VERSION 5.8 ;
BUSBITCHARS "[]" ;
DIVIDERCHAR "/" ;
UNITS
    DATABASE MICRONS 1000 ;
END UNITS

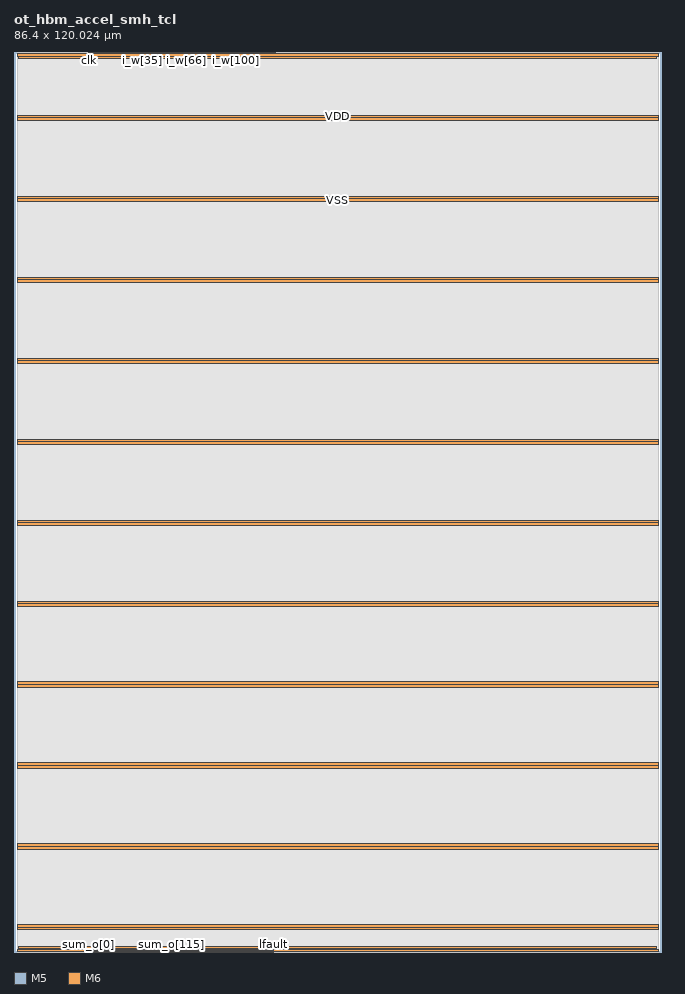
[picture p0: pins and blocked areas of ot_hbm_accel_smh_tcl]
MACRO ot_hbm_accel_smh_tcl
  FOREIGN ot_hbm_accel_smh_tcl 0 0 ;
  CLASS BLOCK ;
  SIZE 86.4 BY 120.024 ;
  PIN clk
    DIRECTION INPUT ;
    USE SIGNAL ;
    PORT
      LAYER M5 ;
        RECT  9.984 119.832 10.008 120.024 ;
    END
  END clk
  PIN i_first
    DIRECTION INPUT ;
    USE SIGNAL ;
    PORT
      LAYER M5 ;
        RECT  10.272 119.832 10.296 120.024 ;
    END
  END i_first
  PIN i_v
    DIRECTION INPUT ;
    USE SIGNAL ;
    PORT
      LAYER M5 ;
        RECT  10.176 119.832 10.2 120.024 ;
    END
  END i_v
  PIN i_w[0]
    DIRECTION INPUT ;
    USE SIGNAL ;
    PORT
      LAYER M5 ;
        RECT  10.368 119.832 10.392 120.024 ;
    END
  END i_w[0]
  PIN i_w[100]
    DIRECTION INPUT ;
    USE SIGNAL ;
    PORT
      LAYER M5 ;
        RECT  29.568 119.832 29.592 120.024 ;
    END
  END i_w[100]
  PIN i_w[101]
    DIRECTION INPUT ;
    USE SIGNAL ;
    PORT
      LAYER M5 ;
        RECT  29.76 119.832 29.784 120.024 ;
    END
  END i_w[101]
  PIN i_w[102]
    DIRECTION INPUT ;
    USE SIGNAL ;
    PORT
      LAYER M5 ;
        RECT  29.952 119.832 29.976 120.024 ;
    END
  END i_w[102]
  PIN i_w[103]
    DIRECTION INPUT ;
    USE SIGNAL ;
    PORT
      LAYER M5 ;
        RECT  30.144 119.832 30.168 120.024 ;
    END
  END i_w[103]
  PIN i_w[104]
    DIRECTION INPUT ;
    USE SIGNAL ;
    PORT
      LAYER M5 ;
        RECT  30.336 119.832 30.36 120.024 ;
    END
  END i_w[104]
  PIN i_w[105]
    DIRECTION INPUT ;
    USE SIGNAL ;
    PORT
      LAYER M5 ;
        RECT  30.528 119.832 30.552 120.024 ;
    END
  END i_w[105]
  PIN i_w[106]
    DIRECTION INPUT ;
    USE SIGNAL ;
    PORT
      LAYER M5 ;
        RECT  30.72 119.832 30.744 120.024 ;
    END
  END i_w[106]
  PIN i_w[107]
    DIRECTION INPUT ;
    USE SIGNAL ;
    PORT
      LAYER M5 ;
        RECT  30.912 119.832 30.936 120.024 ;
    END
  END i_w[107]
  PIN i_w[108]
    DIRECTION INPUT ;
    USE SIGNAL ;
    PORT
      LAYER M5 ;
        RECT  31.104 119.832 31.128 120.024 ;
    END
  END i_w[108]
  PIN i_w[109]
    DIRECTION INPUT ;
    USE SIGNAL ;
    PORT
      LAYER M5 ;
        RECT  31.296 119.832 31.32 120.024 ;
    END
  END i_w[109]
  PIN i_w[10]
    DIRECTION INPUT ;
    USE SIGNAL ;
    PORT
      LAYER M5 ;
        RECT  12.288 119.832 12.312 120.024 ;
    END
  END i_w[10]
  PIN i_w[110]
    DIRECTION INPUT ;
    USE SIGNAL ;
    PORT
      LAYER M5 ;
        RECT  31.488 119.832 31.512 120.024 ;
    END
  END i_w[110]
  PIN i_w[111]
    DIRECTION INPUT ;
    USE SIGNAL ;
    PORT
      LAYER M5 ;
        RECT  31.68 119.832 31.704 120.024 ;
    END
  END i_w[111]
  PIN i_w[112]
    DIRECTION INPUT ;
    USE SIGNAL ;
    PORT
      LAYER M5 ;
        RECT  31.872 119.832 31.896 120.024 ;
    END
  END i_w[112]
  PIN i_w[113]
    DIRECTION INPUT ;
    USE SIGNAL ;
    PORT
      LAYER M5 ;
        RECT  32.064 119.832 32.088 120.024 ;
    END
  END i_w[113]
  PIN i_w[114]
    DIRECTION INPUT ;
    USE SIGNAL ;
    PORT
      LAYER M5 ;
        RECT  32.256 119.832 32.28 120.024 ;
    END
  END i_w[114]
  PIN i_w[115]
    DIRECTION INPUT ;
    USE SIGNAL ;
    PORT
      LAYER M5 ;
        RECT  32.448 119.832 32.472 120.024 ;
    END
  END i_w[115]
  PIN i_w[116]
    DIRECTION INPUT ;
    USE SIGNAL ;
    PORT
      LAYER M5 ;
        RECT  32.64 119.832 32.664 120.024 ;
    END
  END i_w[116]
  PIN i_w[117]
    DIRECTION INPUT ;
    USE SIGNAL ;
    PORT
      LAYER M5 ;
        RECT  32.832 119.832 32.856 120.024 ;
    END
  END i_w[117]
  PIN i_w[118]
    DIRECTION INPUT ;
    USE SIGNAL ;
    PORT
      LAYER M5 ;
        RECT  33.024 119.832 33.048 120.024 ;
    END
  END i_w[118]
  PIN i_w[119]
    DIRECTION INPUT ;
    USE SIGNAL ;
    PORT
      LAYER M5 ;
        RECT  33.216 119.832 33.24 120.024 ;
    END
  END i_w[119]
  PIN i_w[11]
    DIRECTION INPUT ;
    USE SIGNAL ;
    PORT
      LAYER M5 ;
        RECT  12.48 119.832 12.504 120.024 ;
    END
  END i_w[11]
  PIN i_w[120]
    DIRECTION INPUT ;
    USE SIGNAL ;
    PORT
      LAYER M5 ;
        RECT  33.408 119.832 33.432 120.024 ;
    END
  END i_w[120]
  PIN i_w[121]
    DIRECTION INPUT ;
    USE SIGNAL ;
    PORT
      LAYER M5 ;
        RECT  33.6 119.832 33.624 120.024 ;
    END
  END i_w[121]
  PIN i_w[122]
    DIRECTION INPUT ;
    USE SIGNAL ;
    PORT
      LAYER M5 ;
        RECT  33.792 119.832 33.816 120.024 ;
    END
  END i_w[122]
  PIN i_w[123]
    DIRECTION INPUT ;
    USE SIGNAL ;
    PORT
      LAYER M5 ;
        RECT  33.984 119.832 34.008 120.024 ;
    END
  END i_w[123]
  PIN i_w[124]
    DIRECTION INPUT ;
    USE SIGNAL ;
    PORT
      LAYER M5 ;
        RECT  34.176 119.832 34.2 120.024 ;
    END
  END i_w[124]
  PIN i_w[125]
    DIRECTION INPUT ;
    USE SIGNAL ;
    PORT
      LAYER M5 ;
        RECT  34.368 119.832 34.392 120.024 ;
    END
  END i_w[125]
  PIN i_w[126]
    DIRECTION INPUT ;
    USE SIGNAL ;
    PORT
      LAYER M5 ;
        RECT  34.56 119.832 34.584 120.024 ;
    END
  END i_w[126]
  PIN i_w[127]
    DIRECTION INPUT ;
    USE SIGNAL ;
    PORT
      LAYER M5 ;
        RECT  34.752 119.832 34.776 120.024 ;
    END
  END i_w[127]
  PIN i_w[12]
    DIRECTION INPUT ;
    USE SIGNAL ;
    PORT
      LAYER M5 ;
        RECT  12.672 119.832 12.696 120.024 ;
    END
  END i_w[12]
  PIN i_w[13]
    DIRECTION INPUT ;
    USE SIGNAL ;
    PORT
      LAYER M5 ;
        RECT  12.864 119.832 12.888 120.024 ;
    END
  END i_w[13]
  PIN i_w[14]
    DIRECTION INPUT ;
    USE SIGNAL ;
    PORT
      LAYER M5 ;
        RECT  13.056 119.832 13.08 120.024 ;
    END
  END i_w[14]
  PIN i_w[15]
    DIRECTION INPUT ;
    USE SIGNAL ;
    PORT
      LAYER M5 ;
        RECT  13.248 119.832 13.272 120.024 ;
    END
  END i_w[15]
  PIN i_w[16]
    DIRECTION INPUT ;
    USE SIGNAL ;
    PORT
      LAYER M5 ;
        RECT  13.44 119.832 13.464 120.024 ;
    END
  END i_w[16]
  PIN i_w[17]
    DIRECTION INPUT ;
    USE SIGNAL ;
    PORT
      LAYER M5 ;
        RECT  13.632 119.832 13.656 120.024 ;
    END
  END i_w[17]
  PIN i_w[18]
    DIRECTION INPUT ;
    USE SIGNAL ;
    PORT
      LAYER M5 ;
        RECT  13.824 119.832 13.848 120.024 ;
    END
  END i_w[18]
  PIN i_w[19]
    DIRECTION INPUT ;
    USE SIGNAL ;
    PORT
      LAYER M5 ;
        RECT  14.016 119.832 14.04 120.024 ;
    END
  END i_w[19]
  PIN i_w[1]
    DIRECTION INPUT ;
    USE SIGNAL ;
    PORT
      LAYER M5 ;
        RECT  10.56 119.832 10.584 120.024 ;
    END
  END i_w[1]
  PIN i_w[20]
    DIRECTION INPUT ;
    USE SIGNAL ;
    PORT
      LAYER M5 ;
        RECT  14.208 119.832 14.232 120.024 ;
    END
  END i_w[20]
  PIN i_w[21]
    DIRECTION INPUT ;
    USE SIGNAL ;
    PORT
      LAYER M5 ;
        RECT  14.4 119.832 14.424 120.024 ;
    END
  END i_w[21]
  PIN i_w[22]
    DIRECTION INPUT ;
    USE SIGNAL ;
    PORT
      LAYER M5 ;
        RECT  14.592 119.832 14.616 120.024 ;
    END
  END i_w[22]
  PIN i_w[23]
    DIRECTION INPUT ;
    USE SIGNAL ;
    PORT
      LAYER M5 ;
        RECT  14.784 119.832 14.808 120.024 ;
    END
  END i_w[23]
  PIN i_w[24]
    DIRECTION INPUT ;
    USE SIGNAL ;
    PORT
      LAYER M5 ;
        RECT  14.976 119.832 15 120.024 ;
    END
  END i_w[24]
  PIN i_w[25]
    DIRECTION INPUT ;
    USE SIGNAL ;
    PORT
      LAYER M5 ;
        RECT  15.168 119.832 15.192 120.024 ;
    END
  END i_w[25]
  PIN i_w[26]
    DIRECTION INPUT ;
    USE SIGNAL ;
    PORT
      LAYER M5 ;
        RECT  15.36 119.832 15.384 120.024 ;
    END
  END i_w[26]
  PIN i_w[27]
    DIRECTION INPUT ;
    USE SIGNAL ;
    PORT
      LAYER M5 ;
        RECT  15.552 119.832 15.576 120.024 ;
    END
  END i_w[27]
  PIN i_w[28]
    DIRECTION INPUT ;
    USE SIGNAL ;
    PORT
      LAYER M5 ;
        RECT  15.744 119.832 15.768 120.024 ;
    END
  END i_w[28]
  PIN i_w[29]
    DIRECTION INPUT ;
    USE SIGNAL ;
    PORT
      LAYER M5 ;
        RECT  15.936 119.832 15.96 120.024 ;
    END
  END i_w[29]
  PIN i_w[2]
    DIRECTION INPUT ;
    USE SIGNAL ;
    PORT
      LAYER M5 ;
        RECT  10.752 119.832 10.776 120.024 ;
    END
  END i_w[2]
  PIN i_w[30]
    DIRECTION INPUT ;
    USE SIGNAL ;
    PORT
      LAYER M5 ;
        RECT  16.128 119.832 16.152 120.024 ;
    END
  END i_w[30]
  PIN i_w[31]
    DIRECTION INPUT ;
    USE SIGNAL ;
    PORT
      LAYER M5 ;
        RECT  16.32 119.832 16.344 120.024 ;
    END
  END i_w[31]
  PIN i_w[32]
    DIRECTION INPUT ;
    USE SIGNAL ;
    PORT
      LAYER M5 ;
        RECT  16.512 119.832 16.536 120.024 ;
    END
  END i_w[32]
  PIN i_w[33]
    DIRECTION INPUT ;
    USE SIGNAL ;
    PORT
      LAYER M5 ;
        RECT  16.704 119.832 16.728 120.024 ;
    END
  END i_w[33]
  PIN i_w[34]
    DIRECTION INPUT ;
    USE SIGNAL ;
    PORT
      LAYER M5 ;
        RECT  16.896 119.832 16.92 120.024 ;
    END
  END i_w[34]
  PIN i_w[35]
    DIRECTION INPUT ;
    USE SIGNAL ;
    PORT
      LAYER M5 ;
        RECT  17.088 119.832 17.112 120.024 ;
    END
  END i_w[35]
  PIN i_w[36]
    DIRECTION INPUT ;
    USE SIGNAL ;
    PORT
      LAYER M5 ;
        RECT  17.28 119.832 17.304 120.024 ;
    END
  END i_w[36]
  PIN i_w[37]
    DIRECTION INPUT ;
    USE SIGNAL ;
    PORT
      LAYER M5 ;
        RECT  17.472 119.832 17.496 120.024 ;
    END
  END i_w[37]
  PIN i_w[38]
    DIRECTION INPUT ;
    USE SIGNAL ;
    PORT
      LAYER M5 ;
        RECT  17.664 119.832 17.688 120.024 ;
    END
  END i_w[38]
  PIN i_w[39]
    DIRECTION INPUT ;
    USE SIGNAL ;
    PORT
      LAYER M5 ;
        RECT  17.856 119.832 17.88 120.024 ;
    END
  END i_w[39]
  PIN i_w[3]
    DIRECTION INPUT ;
    USE SIGNAL ;
    PORT
      LAYER M5 ;
        RECT  10.944 119.832 10.968 120.024 ;
    END
  END i_w[3]
  PIN i_w[40]
    DIRECTION INPUT ;
    USE SIGNAL ;
    PORT
      LAYER M5 ;
        RECT  18.048 119.832 18.072 120.024 ;
    END
  END i_w[40]
  PIN i_w[41]
    DIRECTION INPUT ;
    USE SIGNAL ;
    PORT
      LAYER M5 ;
        RECT  18.24 119.832 18.264 120.024 ;
    END
  END i_w[41]
  PIN i_w[42]
    DIRECTION INPUT ;
    USE SIGNAL ;
    PORT
      LAYER M5 ;
        RECT  18.432 119.832 18.456 120.024 ;
    END
  END i_w[42]
  PIN i_w[43]
    DIRECTION INPUT ;
    USE SIGNAL ;
    PORT
      LAYER M5 ;
        RECT  18.624 119.832 18.648 120.024 ;
    END
  END i_w[43]
  PIN i_w[44]
    DIRECTION INPUT ;
    USE SIGNAL ;
    PORT
      LAYER M5 ;
        RECT  18.816 119.832 18.84 120.024 ;
    END
  END i_w[44]
  PIN i_w[45]
    DIRECTION INPUT ;
    USE SIGNAL ;
    PORT
      LAYER M5 ;
        RECT  19.008 119.832 19.032 120.024 ;
    END
  END i_w[45]
  PIN i_w[46]
    DIRECTION INPUT ;
    USE SIGNAL ;
    PORT
      LAYER M5 ;
        RECT  19.2 119.832 19.224 120.024 ;
    END
  END i_w[46]
  PIN i_w[47]
    DIRECTION INPUT ;
    USE SIGNAL ;
    PORT
      LAYER M5 ;
        RECT  19.392 119.832 19.416 120.024 ;
    END
  END i_w[47]
  PIN i_w[48]
    DIRECTION INPUT ;
    USE SIGNAL ;
    PORT
      LAYER M5 ;
        RECT  19.584 119.832 19.608 120.024 ;
    END
  END i_w[48]
  PIN i_w[49]
    DIRECTION INPUT ;
    USE SIGNAL ;
    PORT
      LAYER M5 ;
        RECT  19.776 119.832 19.8 120.024 ;
    END
  END i_w[49]
  PIN i_w[4]
    DIRECTION INPUT ;
    USE SIGNAL ;
    PORT
      LAYER M5 ;
        RECT  11.136 119.832 11.16 120.024 ;
    END
  END i_w[4]
  PIN i_w[50]
    DIRECTION INPUT ;
    USE SIGNAL ;
    PORT
      LAYER M5 ;
        RECT  19.968 119.832 19.992 120.024 ;
    END
  END i_w[50]
  PIN i_w[51]
    DIRECTION INPUT ;
    USE SIGNAL ;
    PORT
      LAYER M5 ;
        RECT  20.16 119.832 20.184 120.024 ;
    END
  END i_w[51]
  PIN i_w[52]
    DIRECTION INPUT ;
    USE SIGNAL ;
    PORT
      LAYER M5 ;
        RECT  20.352 119.832 20.376 120.024 ;
    END
  END i_w[52]
  PIN i_w[53]
    DIRECTION INPUT ;
    USE SIGNAL ;
    PORT
      LAYER M5 ;
        RECT  20.544 119.832 20.568 120.024 ;
    END
  END i_w[53]
  PIN i_w[54]
    DIRECTION INPUT ;
    USE SIGNAL ;
    PORT
      LAYER M5 ;
        RECT  20.736 119.832 20.76 120.024 ;
    END
  END i_w[54]
  PIN i_w[55]
    DIRECTION INPUT ;
    USE SIGNAL ;
    PORT
      LAYER M5 ;
        RECT  20.928 119.832 20.952 120.024 ;
    END
  END i_w[55]
  PIN i_w[56]
    DIRECTION INPUT ;
    USE SIGNAL ;
    PORT
      LAYER M5 ;
        RECT  21.12 119.832 21.144 120.024 ;
    END
  END i_w[56]
  PIN i_w[57]
    DIRECTION INPUT ;
    USE SIGNAL ;
    PORT
      LAYER M5 ;
        RECT  21.312 119.832 21.336 120.024 ;
    END
  END i_w[57]
  PIN i_w[58]
    DIRECTION INPUT ;
    USE SIGNAL ;
    PORT
      LAYER M5 ;
        RECT  21.504 119.832 21.528 120.024 ;
    END
  END i_w[58]
  PIN i_w[59]
    DIRECTION INPUT ;
    USE SIGNAL ;
    PORT
      LAYER M5 ;
        RECT  21.696 119.832 21.72 120.024 ;
    END
  END i_w[59]
  PIN i_w[5]
    DIRECTION INPUT ;
    USE SIGNAL ;
    PORT
      LAYER M5 ;
        RECT  11.328 119.832 11.352 120.024 ;
    END
  END i_w[5]
  PIN i_w[60]
    DIRECTION INPUT ;
    USE SIGNAL ;
    PORT
      LAYER M5 ;
        RECT  21.888 119.832 21.912 120.024 ;
    END
  END i_w[60]
  PIN i_w[61]
    DIRECTION INPUT ;
    USE SIGNAL ;
    PORT
      LAYER M5 ;
        RECT  22.08 119.832 22.104 120.024 ;
    END
  END i_w[61]
  PIN i_w[62]
    DIRECTION INPUT ;
    USE SIGNAL ;
    PORT
      LAYER M5 ;
        RECT  22.272 119.832 22.296 120.024 ;
    END
  END i_w[62]
  PIN i_w[63]
    DIRECTION INPUT ;
    USE SIGNAL ;
    PORT
      LAYER M5 ;
        RECT  22.464 119.832 22.488 120.024 ;
    END
  END i_w[63]
  PIN i_w[64]
    DIRECTION INPUT ;
    USE SIGNAL ;
    PORT
      LAYER M5 ;
        RECT  22.656 119.832 22.68 120.024 ;
    END
  END i_w[64]
  PIN i_w[65]
    DIRECTION INPUT ;
    USE SIGNAL ;
    PORT
      LAYER M5 ;
        RECT  22.848 119.832 22.872 120.024 ;
    END
  END i_w[65]
  PIN i_w[66]
    DIRECTION INPUT ;
    USE SIGNAL ;
    PORT
      LAYER M5 ;
        RECT  23.04 119.832 23.064 120.024 ;
    END
  END i_w[66]
  PIN i_w[67]
    DIRECTION INPUT ;
    USE SIGNAL ;
    PORT
      LAYER M5 ;
        RECT  23.232 119.832 23.256 120.024 ;
    END
  END i_w[67]
  PIN i_w[68]
    DIRECTION INPUT ;
    USE SIGNAL ;
    PORT
      LAYER M5 ;
        RECT  23.424 119.832 23.448 120.024 ;
    END
  END i_w[68]
  PIN i_w[69]
    DIRECTION INPUT ;
    USE SIGNAL ;
    PORT
      LAYER M5 ;
        RECT  23.616 119.832 23.64 120.024 ;
    END
  END i_w[69]
  PIN i_w[6]
    DIRECTION INPUT ;
    USE SIGNAL ;
    PORT
      LAYER M5 ;
        RECT  11.52 119.832 11.544 120.024 ;
    END
  END i_w[6]
  PIN i_w[70]
    DIRECTION INPUT ;
    USE SIGNAL ;
    PORT
      LAYER M5 ;
        RECT  23.808 119.832 23.832 120.024 ;
    END
  END i_w[70]
  PIN i_w[71]
    DIRECTION INPUT ;
    USE SIGNAL ;
    PORT
      LAYER M5 ;
        RECT  24 119.832 24.024 120.024 ;
    END
  END i_w[71]
  PIN i_w[72]
    DIRECTION INPUT ;
    USE SIGNAL ;
    PORT
      LAYER M5 ;
        RECT  24.192 119.832 24.216 120.024 ;
    END
  END i_w[72]
  PIN i_w[73]
    DIRECTION INPUT ;
    USE SIGNAL ;
    PORT
      LAYER M5 ;
        RECT  24.384 119.832 24.408 120.024 ;
    END
  END i_w[73]
  PIN i_w[74]
    DIRECTION INPUT ;
    USE SIGNAL ;
    PORT
      LAYER M5 ;
        RECT  24.576 119.832 24.6 120.024 ;
    END
  END i_w[74]
  PIN i_w[75]
    DIRECTION INPUT ;
    USE SIGNAL ;
    PORT
      LAYER M5 ;
        RECT  24.768 119.832 24.792 120.024 ;
    END
  END i_w[75]
  PIN i_w[76]
    DIRECTION INPUT ;
    USE SIGNAL ;
    PORT
      LAYER M5 ;
        RECT  24.96 119.832 24.984 120.024 ;
    END
  END i_w[76]
  PIN i_w[77]
    DIRECTION INPUT ;
    USE SIGNAL ;
    PORT
      LAYER M5 ;
        RECT  25.152 119.832 25.176 120.024 ;
    END
  END i_w[77]
  PIN i_w[78]
    DIRECTION INPUT ;
    USE SIGNAL ;
    PORT
      LAYER M5 ;
        RECT  25.344 119.832 25.368 120.024 ;
    END
  END i_w[78]
  PIN i_w[79]
    DIRECTION INPUT ;
    USE SIGNAL ;
    PORT
      LAYER M5 ;
        RECT  25.536 119.832 25.56 120.024 ;
    END
  END i_w[79]
  PIN i_w[7]
    DIRECTION INPUT ;
    USE SIGNAL ;
    PORT
      LAYER M5 ;
        RECT  11.712 119.832 11.736 120.024 ;
    END
  END i_w[7]
  PIN i_w[80]
    DIRECTION INPUT ;
    USE SIGNAL ;
    PORT
      LAYER M5 ;
        RECT  25.728 119.832 25.752 120.024 ;
    END
  END i_w[80]
  PIN i_w[81]
    DIRECTION INPUT ;
    USE SIGNAL ;
    PORT
      LAYER M5 ;
        RECT  25.92 119.832 25.944 120.024 ;
    END
  END i_w[81]
  PIN i_w[82]
    DIRECTION INPUT ;
    USE SIGNAL ;
    PORT
      LAYER M5 ;
        RECT  26.112 119.832 26.136 120.024 ;
    END
  END i_w[82]
  PIN i_w[83]
    DIRECTION INPUT ;
    USE SIGNAL ;
    PORT
      LAYER M5 ;
        RECT  26.304 119.832 26.328 120.024 ;
    END
  END i_w[83]
  PIN i_w[84]
    DIRECTION INPUT ;
    USE SIGNAL ;
    PORT
      LAYER M5 ;
        RECT  26.496 119.832 26.52 120.024 ;
    END
  END i_w[84]
  PIN i_w[85]
    DIRECTION INPUT ;
    USE SIGNAL ;
    PORT
      LAYER M5 ;
        RECT  26.688 119.832 26.712 120.024 ;
    END
  END i_w[85]
  PIN i_w[86]
    DIRECTION INPUT ;
    USE SIGNAL ;
    PORT
      LAYER M5 ;
        RECT  26.88 119.832 26.904 120.024 ;
    END
  END i_w[86]
  PIN i_w[87]
    DIRECTION INPUT ;
    USE SIGNAL ;
    PORT
      LAYER M5 ;
        RECT  27.072 119.832 27.096 120.024 ;
    END
  END i_w[87]
  PIN i_w[88]
    DIRECTION INPUT ;
    USE SIGNAL ;
    PORT
      LAYER M5 ;
        RECT  27.264 119.832 27.288 120.024 ;
    END
  END i_w[88]
  PIN i_w[89]
    DIRECTION INPUT ;
    USE SIGNAL ;
    PORT
      LAYER M5 ;
        RECT  27.456 119.832 27.48 120.024 ;
    END
  END i_w[89]
  PIN i_w[8]
    DIRECTION INPUT ;
    USE SIGNAL ;
    PORT
      LAYER M5 ;
        RECT  11.904 119.832 11.928 120.024 ;
    END
  END i_w[8]
  PIN i_w[90]
    DIRECTION INPUT ;
    USE SIGNAL ;
    PORT
      LAYER M5 ;
        RECT  27.648 119.832 27.672 120.024 ;
    END
  END i_w[90]
  PIN i_w[91]
    DIRECTION INPUT ;
    USE SIGNAL ;
    PORT
      LAYER M5 ;
        RECT  27.84 119.832 27.864 120.024 ;
    END
  END i_w[91]
  PIN i_w[92]
    DIRECTION INPUT ;
    USE SIGNAL ;
    PORT
      LAYER M5 ;
        RECT  28.032 119.832 28.056 120.024 ;
    END
  END i_w[92]
  PIN i_w[93]
    DIRECTION INPUT ;
    USE SIGNAL ;
    PORT
      LAYER M5 ;
        RECT  28.224 119.832 28.248 120.024 ;
    END
  END i_w[93]
  PIN i_w[94]
    DIRECTION INPUT ;
    USE SIGNAL ;
    PORT
      LAYER M5 ;
        RECT  28.416 119.832 28.44 120.024 ;
    END
  END i_w[94]
  PIN i_w[95]
    DIRECTION INPUT ;
    USE SIGNAL ;
    PORT
      LAYER M5 ;
        RECT  28.608 119.832 28.632 120.024 ;
    END
  END i_w[95]
  PIN i_w[96]
    DIRECTION INPUT ;
    USE SIGNAL ;
    PORT
      LAYER M5 ;
        RECT  28.8 119.832 28.824 120.024 ;
    END
  END i_w[96]
  PIN i_w[97]
    DIRECTION INPUT ;
    USE SIGNAL ;
    PORT
      LAYER M5 ;
        RECT  28.992 119.832 29.016 120.024 ;
    END
  END i_w[97]
  PIN i_w[98]
    DIRECTION INPUT ;
    USE SIGNAL ;
    PORT
      LAYER M5 ;
        RECT  29.184 119.832 29.208 120.024 ;
    END
  END i_w[98]
  PIN i_w[99]
    DIRECTION INPUT ;
    USE SIGNAL ;
    PORT
      LAYER M5 ;
        RECT  29.376 119.832 29.4 120.024 ;
    END
  END i_w[99]
  PIN i_w[9]
    DIRECTION INPUT ;
    USE SIGNAL ;
    PORT
      LAYER M5 ;
        RECT  12.096 119.832 12.12 120.024 ;
    END
  END i_w[9]
  PIN i_x[0]
    DIRECTION INPUT ;
    USE SIGNAL ;
    PORT
      LAYER M5 ;
        RECT  10.464 119.832 10.488 120.024 ;
    END
  END i_x[0]
  PIN i_x[100]
    DIRECTION INPUT ;
    USE SIGNAL ;
    PORT
      LAYER M5 ;
        RECT  29.664 119.832 29.688 120.024 ;
    END
  END i_x[100]
  PIN i_x[101]
    DIRECTION INPUT ;
    USE SIGNAL ;
    PORT
      LAYER M5 ;
        RECT  29.856 119.832 29.88 120.024 ;
    END
  END i_x[101]
  PIN i_x[102]
    DIRECTION INPUT ;
    USE SIGNAL ;
    PORT
      LAYER M5 ;
        RECT  30.048 119.832 30.072 120.024 ;
    END
  END i_x[102]
  PIN i_x[103]
    DIRECTION INPUT ;
    USE SIGNAL ;
    PORT
      LAYER M5 ;
        RECT  30.24 119.832 30.264 120.024 ;
    END
  END i_x[103]
  PIN i_x[104]
    DIRECTION INPUT ;
    USE SIGNAL ;
    PORT
      LAYER M5 ;
        RECT  30.432 119.832 30.456 120.024 ;
    END
  END i_x[104]
  PIN i_x[105]
    DIRECTION INPUT ;
    USE SIGNAL ;
    PORT
      LAYER M5 ;
        RECT  30.624 119.832 30.648 120.024 ;
    END
  END i_x[105]
  PIN i_x[106]
    DIRECTION INPUT ;
    USE SIGNAL ;
    PORT
      LAYER M5 ;
        RECT  30.816 119.832 30.84 120.024 ;
    END
  END i_x[106]
  PIN i_x[107]
    DIRECTION INPUT ;
    USE SIGNAL ;
    PORT
      LAYER M5 ;
        RECT  31.008 119.832 31.032 120.024 ;
    END
  END i_x[107]
  PIN i_x[108]
    DIRECTION INPUT ;
    USE SIGNAL ;
    PORT
      LAYER M5 ;
        RECT  31.2 119.832 31.224 120.024 ;
    END
  END i_x[108]
  PIN i_x[109]
    DIRECTION INPUT ;
    USE SIGNAL ;
    PORT
      LAYER M5 ;
        RECT  31.392 119.832 31.416 120.024 ;
    END
  END i_x[109]
  PIN i_x[10]
    DIRECTION INPUT ;
    USE SIGNAL ;
    PORT
      LAYER M5 ;
        RECT  12.384 119.832 12.408 120.024 ;
    END
  END i_x[10]
  PIN i_x[110]
    DIRECTION INPUT ;
    USE SIGNAL ;
    PORT
      LAYER M5 ;
        RECT  31.584 119.832 31.608 120.024 ;
    END
  END i_x[110]
  PIN i_x[111]
    DIRECTION INPUT ;
    USE SIGNAL ;
    PORT
      LAYER M5 ;
        RECT  31.776 119.832 31.8 120.024 ;
    END
  END i_x[111]
  PIN i_x[112]
    DIRECTION INPUT ;
    USE SIGNAL ;
    PORT
      LAYER M5 ;
        RECT  31.968 119.832 31.992 120.024 ;
    END
  END i_x[112]
  PIN i_x[113]
    DIRECTION INPUT ;
    USE SIGNAL ;
    PORT
      LAYER M5 ;
        RECT  32.16 119.832 32.184 120.024 ;
    END
  END i_x[113]
  PIN i_x[114]
    DIRECTION INPUT ;
    USE SIGNAL ;
    PORT
      LAYER M5 ;
        RECT  32.352 119.832 32.376 120.024 ;
    END
  END i_x[114]
  PIN i_x[115]
    DIRECTION INPUT ;
    USE SIGNAL ;
    PORT
      LAYER M5 ;
        RECT  32.544 119.832 32.568 120.024 ;
    END
  END i_x[115]
  PIN i_x[116]
    DIRECTION INPUT ;
    USE SIGNAL ;
    PORT
      LAYER M5 ;
        RECT  32.736 119.832 32.76 120.024 ;
    END
  END i_x[116]
  PIN i_x[117]
    DIRECTION INPUT ;
    USE SIGNAL ;
    PORT
      LAYER M5 ;
        RECT  32.928 119.832 32.952 120.024 ;
    END
  END i_x[117]
  PIN i_x[118]
    DIRECTION INPUT ;
    USE SIGNAL ;
    PORT
      LAYER M5 ;
        RECT  33.12 119.832 33.144 120.024 ;
    END
  END i_x[118]
  PIN i_x[119]
    DIRECTION INPUT ;
    USE SIGNAL ;
    PORT
      LAYER M5 ;
        RECT  33.312 119.832 33.336 120.024 ;
    END
  END i_x[119]
  PIN i_x[11]
    DIRECTION INPUT ;
    USE SIGNAL ;
    PORT
      LAYER M5 ;
        RECT  12.576 119.832 12.6 120.024 ;
    END
  END i_x[11]
  PIN i_x[120]
    DIRECTION INPUT ;
    USE SIGNAL ;
    PORT
      LAYER M5 ;
        RECT  33.504 119.832 33.528 120.024 ;
    END
  END i_x[120]
  PIN i_x[121]
    DIRECTION INPUT ;
    USE SIGNAL ;
    PORT
      LAYER M5 ;
        RECT  33.696 119.832 33.72 120.024 ;
    END
  END i_x[121]
  PIN i_x[122]
    DIRECTION INPUT ;
    USE SIGNAL ;
    PORT
      LAYER M5 ;
        RECT  33.888 119.832 33.912 120.024 ;
    END
  END i_x[122]
  PIN i_x[123]
    DIRECTION INPUT ;
    USE SIGNAL ;
    PORT
      LAYER M5 ;
        RECT  34.08 119.832 34.104 120.024 ;
    END
  END i_x[123]
  PIN i_x[124]
    DIRECTION INPUT ;
    USE SIGNAL ;
    PORT
      LAYER M5 ;
        RECT  34.272 119.832 34.296 120.024 ;
    END
  END i_x[124]
  PIN i_x[125]
    DIRECTION INPUT ;
    USE SIGNAL ;
    PORT
      LAYER M5 ;
        RECT  34.464 119.832 34.488 120.024 ;
    END
  END i_x[125]
  PIN i_x[126]
    DIRECTION INPUT ;
    USE SIGNAL ;
    PORT
      LAYER M5 ;
        RECT  34.656 119.832 34.68 120.024 ;
    END
  END i_x[126]
  PIN i_x[127]
    DIRECTION INPUT ;
    USE SIGNAL ;
    PORT
      LAYER M5 ;
        RECT  34.848 119.832 34.872 120.024 ;
    END
  END i_x[127]
  PIN i_x[12]
    DIRECTION INPUT ;
    USE SIGNAL ;
    PORT
      LAYER M5 ;
        RECT  12.768 119.832 12.792 120.024 ;
    END
  END i_x[12]
  PIN i_x[13]
    DIRECTION INPUT ;
    USE SIGNAL ;
    PORT
      LAYER M5 ;
        RECT  12.96 119.832 12.984 120.024 ;
    END
  END i_x[13]
  PIN i_x[14]
    DIRECTION INPUT ;
    USE SIGNAL ;
    PORT
      LAYER M5 ;
        RECT  13.152 119.832 13.176 120.024 ;
    END
  END i_x[14]
  PIN i_x[15]
    DIRECTION INPUT ;
    USE SIGNAL ;
    PORT
      LAYER M5 ;
        RECT  13.344 119.832 13.368 120.024 ;
    END
  END i_x[15]
  PIN i_x[16]
    DIRECTION INPUT ;
    USE SIGNAL ;
    PORT
      LAYER M5 ;
        RECT  13.536 119.832 13.56 120.024 ;
    END
  END i_x[16]
  PIN i_x[17]
    DIRECTION INPUT ;
    USE SIGNAL ;
    PORT
      LAYER M5 ;
        RECT  13.728 119.832 13.752 120.024 ;
    END
  END i_x[17]
  PIN i_x[18]
    DIRECTION INPUT ;
    USE SIGNAL ;
    PORT
      LAYER M5 ;
        RECT  13.92 119.832 13.944 120.024 ;
    END
  END i_x[18]
  PIN i_x[19]
    DIRECTION INPUT ;
    USE SIGNAL ;
    PORT
      LAYER M5 ;
        RECT  14.112 119.832 14.136 120.024 ;
    END
  END i_x[19]
  PIN i_x[1]
    DIRECTION INPUT ;
    USE SIGNAL ;
    PORT
      LAYER M5 ;
        RECT  10.656 119.832 10.68 120.024 ;
    END
  END i_x[1]
  PIN i_x[20]
    DIRECTION INPUT ;
    USE SIGNAL ;
    PORT
      LAYER M5 ;
        RECT  14.304 119.832 14.328 120.024 ;
    END
  END i_x[20]
  PIN i_x[21]
    DIRECTION INPUT ;
    USE SIGNAL ;
    PORT
      LAYER M5 ;
        RECT  14.496 119.832 14.52 120.024 ;
    END
  END i_x[21]
  PIN i_x[22]
    DIRECTION INPUT ;
    USE SIGNAL ;
    PORT
      LAYER M5 ;
        RECT  14.688 119.832 14.712 120.024 ;
    END
  END i_x[22]
  PIN i_x[23]
    DIRECTION INPUT ;
    USE SIGNAL ;
    PORT
      LAYER M5 ;
        RECT  14.88 119.832 14.904 120.024 ;
    END
  END i_x[23]
  PIN i_x[24]
    DIRECTION INPUT ;
    USE SIGNAL ;
    PORT
      LAYER M5 ;
        RECT  15.072 119.832 15.096 120.024 ;
    END
  END i_x[24]
  PIN i_x[25]
    DIRECTION INPUT ;
    USE SIGNAL ;
    PORT
      LAYER M5 ;
        RECT  15.264 119.832 15.288 120.024 ;
    END
  END i_x[25]
  PIN i_x[26]
    DIRECTION INPUT ;
    USE SIGNAL ;
    PORT
      LAYER M5 ;
        RECT  15.456 119.832 15.48 120.024 ;
    END
  END i_x[26]
  PIN i_x[27]
    DIRECTION INPUT ;
    USE SIGNAL ;
    PORT
      LAYER M5 ;
        RECT  15.648 119.832 15.672 120.024 ;
    END
  END i_x[27]
  PIN i_x[28]
    DIRECTION INPUT ;
    USE SIGNAL ;
    PORT
      LAYER M5 ;
        RECT  15.84 119.832 15.864 120.024 ;
    END
  END i_x[28]
  PIN i_x[29]
    DIRECTION INPUT ;
    USE SIGNAL ;
    PORT
      LAYER M5 ;
        RECT  16.032 119.832 16.056 120.024 ;
    END
  END i_x[29]
  PIN i_x[2]
    DIRECTION INPUT ;
    USE SIGNAL ;
    PORT
      LAYER M5 ;
        RECT  10.848 119.832 10.872 120.024 ;
    END
  END i_x[2]
  PIN i_x[30]
    DIRECTION INPUT ;
    USE SIGNAL ;
    PORT
      LAYER M5 ;
        RECT  16.224 119.832 16.248 120.024 ;
    END
  END i_x[30]
  PIN i_x[31]
    DIRECTION INPUT ;
    USE SIGNAL ;
    PORT
      LAYER M5 ;
        RECT  16.416 119.832 16.44 120.024 ;
    END
  END i_x[31]
  PIN i_x[32]
    DIRECTION INPUT ;
    USE SIGNAL ;
    PORT
      LAYER M5 ;
        RECT  16.608 119.832 16.632 120.024 ;
    END
  END i_x[32]
  PIN i_x[33]
    DIRECTION INPUT ;
    USE SIGNAL ;
    PORT
      LAYER M5 ;
        RECT  16.8 119.832 16.824 120.024 ;
    END
  END i_x[33]
  PIN i_x[34]
    DIRECTION INPUT ;
    USE SIGNAL ;
    PORT
      LAYER M5 ;
        RECT  16.992 119.832 17.016 120.024 ;
    END
  END i_x[34]
  PIN i_x[35]
    DIRECTION INPUT ;
    USE SIGNAL ;
    PORT
      LAYER M5 ;
        RECT  17.184 119.832 17.208 120.024 ;
    END
  END i_x[35]
  PIN i_x[36]
    DIRECTION INPUT ;
    USE SIGNAL ;
    PORT
      LAYER M5 ;
        RECT  17.376 119.832 17.4 120.024 ;
    END
  END i_x[36]
  PIN i_x[37]
    DIRECTION INPUT ;
    USE SIGNAL ;
    PORT
      LAYER M5 ;
        RECT  17.568 119.832 17.592 120.024 ;
    END
  END i_x[37]
  PIN i_x[38]
    DIRECTION INPUT ;
    USE SIGNAL ;
    PORT
      LAYER M5 ;
        RECT  17.76 119.832 17.784 120.024 ;
    END
  END i_x[38]
  PIN i_x[39]
    DIRECTION INPUT ;
    USE SIGNAL ;
    PORT
      LAYER M5 ;
        RECT  17.952 119.832 17.976 120.024 ;
    END
  END i_x[39]
  PIN i_x[3]
    DIRECTION INPUT ;
    USE SIGNAL ;
    PORT
      LAYER M5 ;
        RECT  11.04 119.832 11.064 120.024 ;
    END
  END i_x[3]
  PIN i_x[40]
    DIRECTION INPUT ;
    USE SIGNAL ;
    PORT
      LAYER M5 ;
        RECT  18.144 119.832 18.168 120.024 ;
    END
  END i_x[40]
  PIN i_x[41]
    DIRECTION INPUT ;
    USE SIGNAL ;
    PORT
      LAYER M5 ;
        RECT  18.336 119.832 18.36 120.024 ;
    END
  END i_x[41]
  PIN i_x[42]
    DIRECTION INPUT ;
    USE SIGNAL ;
    PORT
      LAYER M5 ;
        RECT  18.528 119.832 18.552 120.024 ;
    END
  END i_x[42]
  PIN i_x[43]
    DIRECTION INPUT ;
    USE SIGNAL ;
    PORT
      LAYER M5 ;
        RECT  18.72 119.832 18.744 120.024 ;
    END
  END i_x[43]
  PIN i_x[44]
    DIRECTION INPUT ;
    USE SIGNAL ;
    PORT
      LAYER M5 ;
        RECT  18.912 119.832 18.936 120.024 ;
    END
  END i_x[44]
  PIN i_x[45]
    DIRECTION INPUT ;
    USE SIGNAL ;
    PORT
      LAYER M5 ;
        RECT  19.104 119.832 19.128 120.024 ;
    END
  END i_x[45]
  PIN i_x[46]
    DIRECTION INPUT ;
    USE SIGNAL ;
    PORT
      LAYER M5 ;
        RECT  19.296 119.832 19.32 120.024 ;
    END
  END i_x[46]
  PIN i_x[47]
    DIRECTION INPUT ;
    USE SIGNAL ;
    PORT
      LAYER M5 ;
        RECT  19.488 119.832 19.512 120.024 ;
    END
  END i_x[47]
  PIN i_x[48]
    DIRECTION INPUT ;
    USE SIGNAL ;
    PORT
      LAYER M5 ;
        RECT  19.68 119.832 19.704 120.024 ;
    END
  END i_x[48]
  PIN i_x[49]
    DIRECTION INPUT ;
    USE SIGNAL ;
    PORT
      LAYER M5 ;
        RECT  19.872 119.832 19.896 120.024 ;
    END
  END i_x[49]
  PIN i_x[4]
    DIRECTION INPUT ;
    USE SIGNAL ;
    PORT
      LAYER M5 ;
        RECT  11.232 119.832 11.256 120.024 ;
    END
  END i_x[4]
  PIN i_x[50]
    DIRECTION INPUT ;
    USE SIGNAL ;
    PORT
      LAYER M5 ;
        RECT  20.064 119.832 20.088 120.024 ;
    END
  END i_x[50]
  PIN i_x[51]
    DIRECTION INPUT ;
    USE SIGNAL ;
    PORT
      LAYER M5 ;
        RECT  20.256 119.832 20.28 120.024 ;
    END
  END i_x[51]
  PIN i_x[52]
    DIRECTION INPUT ;
    USE SIGNAL ;
    PORT
      LAYER M5 ;
        RECT  20.448 119.832 20.472 120.024 ;
    END
  END i_x[52]
  PIN i_x[53]
    DIRECTION INPUT ;
    USE SIGNAL ;
    PORT
      LAYER M5 ;
        RECT  20.64 119.832 20.664 120.024 ;
    END
  END i_x[53]
  PIN i_x[54]
    DIRECTION INPUT ;
    USE SIGNAL ;
    PORT
      LAYER M5 ;
        RECT  20.832 119.832 20.856 120.024 ;
    END
  END i_x[54]
  PIN i_x[55]
    DIRECTION INPUT ;
    USE SIGNAL ;
    PORT
      LAYER M5 ;
        RECT  21.024 119.832 21.048 120.024 ;
    END
  END i_x[55]
  PIN i_x[56]
    DIRECTION INPUT ;
    USE SIGNAL ;
    PORT
      LAYER M5 ;
        RECT  21.216 119.832 21.24 120.024 ;
    END
  END i_x[56]
  PIN i_x[57]
    DIRECTION INPUT ;
    USE SIGNAL ;
    PORT
      LAYER M5 ;
        RECT  21.408 119.832 21.432 120.024 ;
    END
  END i_x[57]
  PIN i_x[58]
    DIRECTION INPUT ;
    USE SIGNAL ;
    PORT
      LAYER M5 ;
        RECT  21.6 119.832 21.624 120.024 ;
    END
  END i_x[58]
  PIN i_x[59]
    DIRECTION INPUT ;
    USE SIGNAL ;
    PORT
      LAYER M5 ;
        RECT  21.792 119.832 21.816 120.024 ;
    END
  END i_x[59]
  PIN i_x[5]
    DIRECTION INPUT ;
    USE SIGNAL ;
    PORT
      LAYER M5 ;
        RECT  11.424 119.832 11.448 120.024 ;
    END
  END i_x[5]
  PIN i_x[60]
    DIRECTION INPUT ;
    USE SIGNAL ;
    PORT
      LAYER M5 ;
        RECT  21.984 119.832 22.008 120.024 ;
    END
  END i_x[60]
  PIN i_x[61]
    DIRECTION INPUT ;
    USE SIGNAL ;
    PORT
      LAYER M5 ;
        RECT  22.176 119.832 22.2 120.024 ;
    END
  END i_x[61]
  PIN i_x[62]
    DIRECTION INPUT ;
    USE SIGNAL ;
    PORT
      LAYER M5 ;
        RECT  22.368 119.832 22.392 120.024 ;
    END
  END i_x[62]
  PIN i_x[63]
    DIRECTION INPUT ;
    USE SIGNAL ;
    PORT
      LAYER M5 ;
        RECT  22.56 119.832 22.584 120.024 ;
    END
  END i_x[63]
  PIN i_x[64]
    DIRECTION INPUT ;
    USE SIGNAL ;
    PORT
      LAYER M5 ;
        RECT  22.752 119.832 22.776 120.024 ;
    END
  END i_x[64]
  PIN i_x[65]
    DIRECTION INPUT ;
    USE SIGNAL ;
    PORT
      LAYER M5 ;
        RECT  22.944 119.832 22.968 120.024 ;
    END
  END i_x[65]
  PIN i_x[66]
    DIRECTION INPUT ;
    USE SIGNAL ;
    PORT
      LAYER M5 ;
        RECT  23.136 119.832 23.16 120.024 ;
    END
  END i_x[66]
  PIN i_x[67]
    DIRECTION INPUT ;
    USE SIGNAL ;
    PORT
      LAYER M5 ;
        RECT  23.328 119.832 23.352 120.024 ;
    END
  END i_x[67]
  PIN i_x[68]
    DIRECTION INPUT ;
    USE SIGNAL ;
    PORT
      LAYER M5 ;
        RECT  23.52 119.832 23.544 120.024 ;
    END
  END i_x[68]
  PIN i_x[69]
    DIRECTION INPUT ;
    USE SIGNAL ;
    PORT
      LAYER M5 ;
        RECT  23.712 119.832 23.736 120.024 ;
    END
  END i_x[69]
  PIN i_x[6]
    DIRECTION INPUT ;
    USE SIGNAL ;
    PORT
      LAYER M5 ;
        RECT  11.616 119.832 11.64 120.024 ;
    END
  END i_x[6]
  PIN i_x[70]
    DIRECTION INPUT ;
    USE SIGNAL ;
    PORT
      LAYER M5 ;
        RECT  23.904 119.832 23.928 120.024 ;
    END
  END i_x[70]
  PIN i_x[71]
    DIRECTION INPUT ;
    USE SIGNAL ;
    PORT
      LAYER M5 ;
        RECT  24.096 119.832 24.12 120.024 ;
    END
  END i_x[71]
  PIN i_x[72]
    DIRECTION INPUT ;
    USE SIGNAL ;
    PORT
      LAYER M5 ;
        RECT  24.288 119.832 24.312 120.024 ;
    END
  END i_x[72]
  PIN i_x[73]
    DIRECTION INPUT ;
    USE SIGNAL ;
    PORT
      LAYER M5 ;
        RECT  24.48 119.832 24.504 120.024 ;
    END
  END i_x[73]
  PIN i_x[74]
    DIRECTION INPUT ;
    USE SIGNAL ;
    PORT
      LAYER M5 ;
        RECT  24.672 119.832 24.696 120.024 ;
    END
  END i_x[74]
  PIN i_x[75]
    DIRECTION INPUT ;
    USE SIGNAL ;
    PORT
      LAYER M5 ;
        RECT  24.864 119.832 24.888 120.024 ;
    END
  END i_x[75]
  PIN i_x[76]
    DIRECTION INPUT ;
    USE SIGNAL ;
    PORT
      LAYER M5 ;
        RECT  25.056 119.832 25.08 120.024 ;
    END
  END i_x[76]
  PIN i_x[77]
    DIRECTION INPUT ;
    USE SIGNAL ;
    PORT
      LAYER M5 ;
        RECT  25.248 119.832 25.272 120.024 ;
    END
  END i_x[77]
  PIN i_x[78]
    DIRECTION INPUT ;
    USE SIGNAL ;
    PORT
      LAYER M5 ;
        RECT  25.44 119.832 25.464 120.024 ;
    END
  END i_x[78]
  PIN i_x[79]
    DIRECTION INPUT ;
    USE SIGNAL ;
    PORT
      LAYER M5 ;
        RECT  25.632 119.832 25.656 120.024 ;
    END
  END i_x[79]
  PIN i_x[7]
    DIRECTION INPUT ;
    USE SIGNAL ;
    PORT
      LAYER M5 ;
        RECT  11.808 119.832 11.832 120.024 ;
    END
  END i_x[7]
  PIN i_x[80]
    DIRECTION INPUT ;
    USE SIGNAL ;
    PORT
      LAYER M5 ;
        RECT  25.824 119.832 25.848 120.024 ;
    END
  END i_x[80]
  PIN i_x[81]
    DIRECTION INPUT ;
    USE SIGNAL ;
    PORT
      LAYER M5 ;
        RECT  26.016 119.832 26.04 120.024 ;
    END
  END i_x[81]
  PIN i_x[82]
    DIRECTION INPUT ;
    USE SIGNAL ;
    PORT
      LAYER M5 ;
        RECT  26.208 119.832 26.232 120.024 ;
    END
  END i_x[82]
  PIN i_x[83]
    DIRECTION INPUT ;
    USE SIGNAL ;
    PORT
      LAYER M5 ;
        RECT  26.4 119.832 26.424 120.024 ;
    END
  END i_x[83]
  PIN i_x[84]
    DIRECTION INPUT ;
    USE SIGNAL ;
    PORT
      LAYER M5 ;
        RECT  26.592 119.832 26.616 120.024 ;
    END
  END i_x[84]
  PIN i_x[85]
    DIRECTION INPUT ;
    USE SIGNAL ;
    PORT
      LAYER M5 ;
        RECT  26.784 119.832 26.808 120.024 ;
    END
  END i_x[85]
  PIN i_x[86]
    DIRECTION INPUT ;
    USE SIGNAL ;
    PORT
      LAYER M5 ;
        RECT  26.976 119.832 27 120.024 ;
    END
  END i_x[86]
  PIN i_x[87]
    DIRECTION INPUT ;
    USE SIGNAL ;
    PORT
      LAYER M5 ;
        RECT  27.168 119.832 27.192 120.024 ;
    END
  END i_x[87]
  PIN i_x[88]
    DIRECTION INPUT ;
    USE SIGNAL ;
    PORT
      LAYER M5 ;
        RECT  27.36 119.832 27.384 120.024 ;
    END
  END i_x[88]
  PIN i_x[89]
    DIRECTION INPUT ;
    USE SIGNAL ;
    PORT
      LAYER M5 ;
        RECT  27.552 119.832 27.576 120.024 ;
    END
  END i_x[89]
  PIN i_x[8]
    DIRECTION INPUT ;
    USE SIGNAL ;
    PORT
      LAYER M5 ;
        RECT  12 119.832 12.024 120.024 ;
    END
  END i_x[8]
  PIN i_x[90]
    DIRECTION INPUT ;
    USE SIGNAL ;
    PORT
      LAYER M5 ;
        RECT  27.744 119.832 27.768 120.024 ;
    END
  END i_x[90]
  PIN i_x[91]
    DIRECTION INPUT ;
    USE SIGNAL ;
    PORT
      LAYER M5 ;
        RECT  27.936 119.832 27.96 120.024 ;
    END
  END i_x[91]
  PIN i_x[92]
    DIRECTION INPUT ;
    USE SIGNAL ;
    PORT
      LAYER M5 ;
        RECT  28.128 119.832 28.152 120.024 ;
    END
  END i_x[92]
  PIN i_x[93]
    DIRECTION INPUT ;
    USE SIGNAL ;
    PORT
      LAYER M5 ;
        RECT  28.32 119.832 28.344 120.024 ;
    END
  END i_x[93]
  PIN i_x[94]
    DIRECTION INPUT ;
    USE SIGNAL ;
    PORT
      LAYER M5 ;
        RECT  28.512 119.832 28.536 120.024 ;
    END
  END i_x[94]
  PIN i_x[95]
    DIRECTION INPUT ;
    USE SIGNAL ;
    PORT
      LAYER M5 ;
        RECT  28.704 119.832 28.728 120.024 ;
    END
  END i_x[95]
  PIN i_x[96]
    DIRECTION INPUT ;
    USE SIGNAL ;
    PORT
      LAYER M5 ;
        RECT  28.896 119.832 28.92 120.024 ;
    END
  END i_x[96]
  PIN i_x[97]
    DIRECTION INPUT ;
    USE SIGNAL ;
    PORT
      LAYER M5 ;
        RECT  29.088 119.832 29.112 120.024 ;
    END
  END i_x[97]
  PIN i_x[98]
    DIRECTION INPUT ;
    USE SIGNAL ;
    PORT
      LAYER M5 ;
        RECT  29.28 119.832 29.304 120.024 ;
    END
  END i_x[98]
  PIN i_x[99]
    DIRECTION INPUT ;
    USE SIGNAL ;
    PORT
      LAYER M5 ;
        RECT  29.472 119.832 29.496 120.024 ;
    END
  END i_x[99]
  PIN i_x[9]
    DIRECTION INPUT ;
    USE SIGNAL ;
    PORT
      LAYER M5 ;
        RECT  12.192 119.832 12.216 120.024 ;
    END
  END i_x[9]
  PIN lfault
    DIRECTION OUTPUT ;
    USE SIGNAL ;
    PORT
      LAYER M5 ;
        RECT  34.56 0 34.584 0.192 ;
    END
  END lfault
  PIN rst_a
    DIRECTION INPUT ;
    USE SIGNAL ;
    PORT
      LAYER M5 ;
        RECT  10.08 119.832 10.104 120.024 ;
    END
  END rst_a
  PIN sum_o[0]
    DIRECTION OUTPUT ;
    USE SIGNAL ;
    PORT
      LAYER M5 ;
        RECT  9.984 0 10.008 0.192 ;
    END
  END sum_o[0]
  PIN sum_o[100]
    DIRECTION OUTPUT ;
    USE SIGNAL ;
    PORT
      LAYER M5 ;
        RECT  19.584 0 19.608 0.192 ;
    END
  END sum_o[100]
  PIN sum_o[101]
    DIRECTION OUTPUT ;
    USE SIGNAL ;
    PORT
      LAYER M5 ;
        RECT  19.68 0 19.704 0.192 ;
    END
  END sum_o[101]
  PIN sum_o[102]
    DIRECTION OUTPUT ;
    USE SIGNAL ;
    PORT
      LAYER M5 ;
        RECT  19.776 0 19.8 0.192 ;
    END
  END sum_o[102]
  PIN sum_o[103]
    DIRECTION OUTPUT ;
    USE SIGNAL ;
    PORT
      LAYER M5 ;
        RECT  19.872 0 19.896 0.192 ;
    END
  END sum_o[103]
  PIN sum_o[104]
    DIRECTION OUTPUT ;
    USE SIGNAL ;
    PORT
      LAYER M5 ;
        RECT  19.968 0 19.992 0.192 ;
    END
  END sum_o[104]
  PIN sum_o[105]
    DIRECTION OUTPUT ;
    USE SIGNAL ;
    PORT
      LAYER M5 ;
        RECT  20.064 0 20.088 0.192 ;
    END
  END sum_o[105]
  PIN sum_o[106]
    DIRECTION OUTPUT ;
    USE SIGNAL ;
    PORT
      LAYER M5 ;
        RECT  20.16 0 20.184 0.192 ;
    END
  END sum_o[106]
  PIN sum_o[107]
    DIRECTION OUTPUT ;
    USE SIGNAL ;
    PORT
      LAYER M5 ;
        RECT  20.256 0 20.28 0.192 ;
    END
  END sum_o[107]
  PIN sum_o[108]
    DIRECTION OUTPUT ;
    USE SIGNAL ;
    PORT
      LAYER M5 ;
        RECT  20.352 0 20.376 0.192 ;
    END
  END sum_o[108]
  PIN sum_o[109]
    DIRECTION OUTPUT ;
    USE SIGNAL ;
    PORT
      LAYER M5 ;
        RECT  20.448 0 20.472 0.192 ;
    END
  END sum_o[109]
  PIN sum_o[10]
    DIRECTION OUTPUT ;
    USE SIGNAL ;
    PORT
      LAYER M5 ;
        RECT  10.944 0 10.968 0.192 ;
    END
  END sum_o[10]
  PIN sum_o[110]
    DIRECTION OUTPUT ;
    USE SIGNAL ;
    PORT
      LAYER M5 ;
        RECT  20.544 0 20.568 0.192 ;
    END
  END sum_o[110]
  PIN sum_o[111]
    DIRECTION OUTPUT ;
    USE SIGNAL ;
    PORT
      LAYER M5 ;
        RECT  20.64 0 20.664 0.192 ;
    END
  END sum_o[111]
  PIN sum_o[112]
    DIRECTION OUTPUT ;
    USE SIGNAL ;
    PORT
      LAYER M5 ;
        RECT  20.736 0 20.76 0.192 ;
    END
  END sum_o[112]
  PIN sum_o[113]
    DIRECTION OUTPUT ;
    USE SIGNAL ;
    PORT
      LAYER M5 ;
        RECT  20.832 0 20.856 0.192 ;
    END
  END sum_o[113]
  PIN sum_o[114]
    DIRECTION OUTPUT ;
    USE SIGNAL ;
    PORT
      LAYER M5 ;
        RECT  20.928 0 20.952 0.192 ;
    END
  END sum_o[114]
  PIN sum_o[115]
    DIRECTION OUTPUT ;
    USE SIGNAL ;
    PORT
      LAYER M5 ;
        RECT  21.024 0 21.048 0.192 ;
    END
  END sum_o[115]
  PIN sum_o[116]
    DIRECTION OUTPUT ;
    USE SIGNAL ;
    PORT
      LAYER M5 ;
        RECT  21.12 0 21.144 0.192 ;
    END
  END sum_o[116]
  PIN sum_o[117]
    DIRECTION OUTPUT ;
    USE SIGNAL ;
    PORT
      LAYER M5 ;
        RECT  21.216 0 21.24 0.192 ;
    END
  END sum_o[117]
  PIN sum_o[118]
    DIRECTION OUTPUT ;
    USE SIGNAL ;
    PORT
      LAYER M5 ;
        RECT  21.312 0 21.336 0.192 ;
    END
  END sum_o[118]
  PIN sum_o[119]
    DIRECTION OUTPUT ;
    USE SIGNAL ;
    PORT
      LAYER M5 ;
        RECT  21.408 0 21.432 0.192 ;
    END
  END sum_o[119]
  PIN sum_o[11]
    DIRECTION OUTPUT ;
    USE SIGNAL ;
    PORT
      LAYER M5 ;
        RECT  11.04 0 11.064 0.192 ;
    END
  END sum_o[11]
  PIN sum_o[120]
    DIRECTION OUTPUT ;
    USE SIGNAL ;
    PORT
      LAYER M5 ;
        RECT  21.504 0 21.528 0.192 ;
    END
  END sum_o[120]
  PIN sum_o[121]
    DIRECTION OUTPUT ;
    USE SIGNAL ;
    PORT
      LAYER M5 ;
        RECT  21.6 0 21.624 0.192 ;
    END
  END sum_o[121]
  PIN sum_o[122]
    DIRECTION OUTPUT ;
    USE SIGNAL ;
    PORT
      LAYER M5 ;
        RECT  21.696 0 21.72 0.192 ;
    END
  END sum_o[122]
  PIN sum_o[123]
    DIRECTION OUTPUT ;
    USE SIGNAL ;
    PORT
      LAYER M5 ;
        RECT  21.792 0 21.816 0.192 ;
    END
  END sum_o[123]
  PIN sum_o[124]
    DIRECTION OUTPUT ;
    USE SIGNAL ;
    PORT
      LAYER M5 ;
        RECT  21.888 0 21.912 0.192 ;
    END
  END sum_o[124]
  PIN sum_o[125]
    DIRECTION OUTPUT ;
    USE SIGNAL ;
    PORT
      LAYER M5 ;
        RECT  21.984 0 22.008 0.192 ;
    END
  END sum_o[125]
  PIN sum_o[126]
    DIRECTION OUTPUT ;
    USE SIGNAL ;
    PORT
      LAYER M5 ;
        RECT  22.08 0 22.104 0.192 ;
    END
  END sum_o[126]
  PIN sum_o[127]
    DIRECTION OUTPUT ;
    USE SIGNAL ;
    PORT
      LAYER M5 ;
        RECT  22.176 0 22.2 0.192 ;
    END
  END sum_o[127]
  PIN sum_o[128]
    DIRECTION OUTPUT ;
    USE SIGNAL ;
    PORT
      LAYER M5 ;
        RECT  22.272 0 22.296 0.192 ;
    END
  END sum_o[128]
  PIN sum_o[129]
    DIRECTION OUTPUT ;
    USE SIGNAL ;
    PORT
      LAYER M5 ;
        RECT  22.368 0 22.392 0.192 ;
    END
  END sum_o[129]
  PIN sum_o[12]
    DIRECTION OUTPUT ;
    USE SIGNAL ;
    PORT
      LAYER M5 ;
        RECT  11.136 0 11.16 0.192 ;
    END
  END sum_o[12]
  PIN sum_o[130]
    DIRECTION OUTPUT ;
    USE SIGNAL ;
    PORT
      LAYER M5 ;
        RECT  22.464 0 22.488 0.192 ;
    END
  END sum_o[130]
  PIN sum_o[131]
    DIRECTION OUTPUT ;
    USE SIGNAL ;
    PORT
      LAYER M5 ;
        RECT  22.56 0 22.584 0.192 ;
    END
  END sum_o[131]
  PIN sum_o[132]
    DIRECTION OUTPUT ;
    USE SIGNAL ;
    PORT
      LAYER M5 ;
        RECT  22.656 0 22.68 0.192 ;
    END
  END sum_o[132]
  PIN sum_o[133]
    DIRECTION OUTPUT ;
    USE SIGNAL ;
    PORT
      LAYER M5 ;
        RECT  22.752 0 22.776 0.192 ;
    END
  END sum_o[133]
  PIN sum_o[134]
    DIRECTION OUTPUT ;
    USE SIGNAL ;
    PORT
      LAYER M5 ;
        RECT  22.848 0 22.872 0.192 ;
    END
  END sum_o[134]
  PIN sum_o[135]
    DIRECTION OUTPUT ;
    USE SIGNAL ;
    PORT
      LAYER M5 ;
        RECT  22.944 0 22.968 0.192 ;
    END
  END sum_o[135]
  PIN sum_o[136]
    DIRECTION OUTPUT ;
    USE SIGNAL ;
    PORT
      LAYER M5 ;
        RECT  23.04 0 23.064 0.192 ;
    END
  END sum_o[136]
  PIN sum_o[137]
    DIRECTION OUTPUT ;
    USE SIGNAL ;
    PORT
      LAYER M5 ;
        RECT  23.136 0 23.16 0.192 ;
    END
  END sum_o[137]
  PIN sum_o[138]
    DIRECTION OUTPUT ;
    USE SIGNAL ;
    PORT
      LAYER M5 ;
        RECT  23.232 0 23.256 0.192 ;
    END
  END sum_o[138]
  PIN sum_o[139]
    DIRECTION OUTPUT ;
    USE SIGNAL ;
    PORT
      LAYER M5 ;
        RECT  23.328 0 23.352 0.192 ;
    END
  END sum_o[139]
  PIN sum_o[13]
    DIRECTION OUTPUT ;
    USE SIGNAL ;
    PORT
      LAYER M5 ;
        RECT  11.232 0 11.256 0.192 ;
    END
  END sum_o[13]
  PIN sum_o[140]
    DIRECTION OUTPUT ;
    USE SIGNAL ;
    PORT
      LAYER M5 ;
        RECT  23.424 0 23.448 0.192 ;
    END
  END sum_o[140]
  PIN sum_o[141]
    DIRECTION OUTPUT ;
    USE SIGNAL ;
    PORT
      LAYER M5 ;
        RECT  23.52 0 23.544 0.192 ;
    END
  END sum_o[141]
  PIN sum_o[142]
    DIRECTION OUTPUT ;
    USE SIGNAL ;
    PORT
      LAYER M5 ;
        RECT  23.616 0 23.64 0.192 ;
    END
  END sum_o[142]
  PIN sum_o[143]
    DIRECTION OUTPUT ;
    USE SIGNAL ;
    PORT
      LAYER M5 ;
        RECT  23.712 0 23.736 0.192 ;
    END
  END sum_o[143]
  PIN sum_o[144]
    DIRECTION OUTPUT ;
    USE SIGNAL ;
    PORT
      LAYER M5 ;
        RECT  23.808 0 23.832 0.192 ;
    END
  END sum_o[144]
  PIN sum_o[145]
    DIRECTION OUTPUT ;
    USE SIGNAL ;
    PORT
      LAYER M5 ;
        RECT  23.904 0 23.928 0.192 ;
    END
  END sum_o[145]
  PIN sum_o[146]
    DIRECTION OUTPUT ;
    USE SIGNAL ;
    PORT
      LAYER M5 ;
        RECT  24 0 24.024 0.192 ;
    END
  END sum_o[146]
  PIN sum_o[147]
    DIRECTION OUTPUT ;
    USE SIGNAL ;
    PORT
      LAYER M5 ;
        RECT  24.096 0 24.12 0.192 ;
    END
  END sum_o[147]
  PIN sum_o[148]
    DIRECTION OUTPUT ;
    USE SIGNAL ;
    PORT
      LAYER M5 ;
        RECT  24.192 0 24.216 0.192 ;
    END
  END sum_o[148]
  PIN sum_o[149]
    DIRECTION OUTPUT ;
    USE SIGNAL ;
    PORT
      LAYER M5 ;
        RECT  24.288 0 24.312 0.192 ;
    END
  END sum_o[149]
  PIN sum_o[14]
    DIRECTION OUTPUT ;
    USE SIGNAL ;
    PORT
      LAYER M5 ;
        RECT  11.328 0 11.352 0.192 ;
    END
  END sum_o[14]
  PIN sum_o[150]
    DIRECTION OUTPUT ;
    USE SIGNAL ;
    PORT
      LAYER M5 ;
        RECT  24.384 0 24.408 0.192 ;
    END
  END sum_o[150]
  PIN sum_o[151]
    DIRECTION OUTPUT ;
    USE SIGNAL ;
    PORT
      LAYER M5 ;
        RECT  24.48 0 24.504 0.192 ;
    END
  END sum_o[151]
  PIN sum_o[152]
    DIRECTION OUTPUT ;
    USE SIGNAL ;
    PORT
      LAYER M5 ;
        RECT  24.576 0 24.6 0.192 ;
    END
  END sum_o[152]
  PIN sum_o[153]
    DIRECTION OUTPUT ;
    USE SIGNAL ;
    PORT
      LAYER M5 ;
        RECT  24.672 0 24.696 0.192 ;
    END
  END sum_o[153]
  PIN sum_o[154]
    DIRECTION OUTPUT ;
    USE SIGNAL ;
    PORT
      LAYER M5 ;
        RECT  24.768 0 24.792 0.192 ;
    END
  END sum_o[154]
  PIN sum_o[155]
    DIRECTION OUTPUT ;
    USE SIGNAL ;
    PORT
      LAYER M5 ;
        RECT  24.864 0 24.888 0.192 ;
    END
  END sum_o[155]
  PIN sum_o[156]
    DIRECTION OUTPUT ;
    USE SIGNAL ;
    PORT
      LAYER M5 ;
        RECT  24.96 0 24.984 0.192 ;
    END
  END sum_o[156]
  PIN sum_o[157]
    DIRECTION OUTPUT ;
    USE SIGNAL ;
    PORT
      LAYER M5 ;
        RECT  25.056 0 25.08 0.192 ;
    END
  END sum_o[157]
  PIN sum_o[158]
    DIRECTION OUTPUT ;
    USE SIGNAL ;
    PORT
      LAYER M5 ;
        RECT  25.152 0 25.176 0.192 ;
    END
  END sum_o[158]
  PIN sum_o[159]
    DIRECTION OUTPUT ;
    USE SIGNAL ;
    PORT
      LAYER M5 ;
        RECT  25.248 0 25.272 0.192 ;
    END
  END sum_o[159]
  PIN sum_o[15]
    DIRECTION OUTPUT ;
    USE SIGNAL ;
    PORT
      LAYER M5 ;
        RECT  11.424 0 11.448 0.192 ;
    END
  END sum_o[15]
  PIN sum_o[160]
    DIRECTION OUTPUT ;
    USE SIGNAL ;
    PORT
      LAYER M5 ;
        RECT  25.344 0 25.368 0.192 ;
    END
  END sum_o[160]
  PIN sum_o[161]
    DIRECTION OUTPUT ;
    USE SIGNAL ;
    PORT
      LAYER M5 ;
        RECT  25.44 0 25.464 0.192 ;
    END
  END sum_o[161]
  PIN sum_o[162]
    DIRECTION OUTPUT ;
    USE SIGNAL ;
    PORT
      LAYER M5 ;
        RECT  25.536 0 25.56 0.192 ;
    END
  END sum_o[162]
  PIN sum_o[163]
    DIRECTION OUTPUT ;
    USE SIGNAL ;
    PORT
      LAYER M5 ;
        RECT  25.632 0 25.656 0.192 ;
    END
  END sum_o[163]
  PIN sum_o[164]
    DIRECTION OUTPUT ;
    USE SIGNAL ;
    PORT
      LAYER M5 ;
        RECT  25.728 0 25.752 0.192 ;
    END
  END sum_o[164]
  PIN sum_o[165]
    DIRECTION OUTPUT ;
    USE SIGNAL ;
    PORT
      LAYER M5 ;
        RECT  25.824 0 25.848 0.192 ;
    END
  END sum_o[165]
  PIN sum_o[166]
    DIRECTION OUTPUT ;
    USE SIGNAL ;
    PORT
      LAYER M5 ;
        RECT  25.92 0 25.944 0.192 ;
    END
  END sum_o[166]
  PIN sum_o[167]
    DIRECTION OUTPUT ;
    USE SIGNAL ;
    PORT
      LAYER M5 ;
        RECT  26.016 0 26.04 0.192 ;
    END
  END sum_o[167]
  PIN sum_o[168]
    DIRECTION OUTPUT ;
    USE SIGNAL ;
    PORT
      LAYER M5 ;
        RECT  26.112 0 26.136 0.192 ;
    END
  END sum_o[168]
  PIN sum_o[169]
    DIRECTION OUTPUT ;
    USE SIGNAL ;
    PORT
      LAYER M5 ;
        RECT  26.208 0 26.232 0.192 ;
    END
  END sum_o[169]
  PIN sum_o[16]
    DIRECTION OUTPUT ;
    USE SIGNAL ;
    PORT
      LAYER M5 ;
        RECT  11.52 0 11.544 0.192 ;
    END
  END sum_o[16]
  PIN sum_o[170]
    DIRECTION OUTPUT ;
    USE SIGNAL ;
    PORT
      LAYER M5 ;
        RECT  26.304 0 26.328 0.192 ;
    END
  END sum_o[170]
  PIN sum_o[171]
    DIRECTION OUTPUT ;
    USE SIGNAL ;
    PORT
      LAYER M5 ;
        RECT  26.4 0 26.424 0.192 ;
    END
  END sum_o[171]
  PIN sum_o[172]
    DIRECTION OUTPUT ;
    USE SIGNAL ;
    PORT
      LAYER M5 ;
        RECT  26.496 0 26.52 0.192 ;
    END
  END sum_o[172]
  PIN sum_o[173]
    DIRECTION OUTPUT ;
    USE SIGNAL ;
    PORT
      LAYER M5 ;
        RECT  26.592 0 26.616 0.192 ;
    END
  END sum_o[173]
  PIN sum_o[174]
    DIRECTION OUTPUT ;
    USE SIGNAL ;
    PORT
      LAYER M5 ;
        RECT  26.688 0 26.712 0.192 ;
    END
  END sum_o[174]
  PIN sum_o[175]
    DIRECTION OUTPUT ;
    USE SIGNAL ;
    PORT
      LAYER M5 ;
        RECT  26.784 0 26.808 0.192 ;
    END
  END sum_o[175]
  PIN sum_o[176]
    DIRECTION OUTPUT ;
    USE SIGNAL ;
    PORT
      LAYER M5 ;
        RECT  26.88 0 26.904 0.192 ;
    END
  END sum_o[176]
  PIN sum_o[177]
    DIRECTION OUTPUT ;
    USE SIGNAL ;
    PORT
      LAYER M5 ;
        RECT  26.976 0 27 0.192 ;
    END
  END sum_o[177]
  PIN sum_o[178]
    DIRECTION OUTPUT ;
    USE SIGNAL ;
    PORT
      LAYER M5 ;
        RECT  27.072 0 27.096 0.192 ;
    END
  END sum_o[178]
  PIN sum_o[179]
    DIRECTION OUTPUT ;
    USE SIGNAL ;
    PORT
      LAYER M5 ;
        RECT  27.168 0 27.192 0.192 ;
    END
  END sum_o[179]
  PIN sum_o[17]
    DIRECTION OUTPUT ;
    USE SIGNAL ;
    PORT
      LAYER M5 ;
        RECT  11.616 0 11.64 0.192 ;
    END
  END sum_o[17]
  PIN sum_o[180]
    DIRECTION OUTPUT ;
    USE SIGNAL ;
    PORT
      LAYER M5 ;
        RECT  27.264 0 27.288 0.192 ;
    END
  END sum_o[180]
  PIN sum_o[181]
    DIRECTION OUTPUT ;
    USE SIGNAL ;
    PORT
      LAYER M5 ;
        RECT  27.36 0 27.384 0.192 ;
    END
  END sum_o[181]
  PIN sum_o[182]
    DIRECTION OUTPUT ;
    USE SIGNAL ;
    PORT
      LAYER M5 ;
        RECT  27.456 0 27.48 0.192 ;
    END
  END sum_o[182]
  PIN sum_o[183]
    DIRECTION OUTPUT ;
    USE SIGNAL ;
    PORT
      LAYER M5 ;
        RECT  27.552 0 27.576 0.192 ;
    END
  END sum_o[183]
  PIN sum_o[184]
    DIRECTION OUTPUT ;
    USE SIGNAL ;
    PORT
      LAYER M5 ;
        RECT  27.648 0 27.672 0.192 ;
    END
  END sum_o[184]
  PIN sum_o[185]
    DIRECTION OUTPUT ;
    USE SIGNAL ;
    PORT
      LAYER M5 ;
        RECT  27.744 0 27.768 0.192 ;
    END
  END sum_o[185]
  PIN sum_o[186]
    DIRECTION OUTPUT ;
    USE SIGNAL ;
    PORT
      LAYER M5 ;
        RECT  27.84 0 27.864 0.192 ;
    END
  END sum_o[186]
  PIN sum_o[187]
    DIRECTION OUTPUT ;
    USE SIGNAL ;
    PORT
      LAYER M5 ;
        RECT  27.936 0 27.96 0.192 ;
    END
  END sum_o[187]
  PIN sum_o[188]
    DIRECTION OUTPUT ;
    USE SIGNAL ;
    PORT
      LAYER M5 ;
        RECT  28.032 0 28.056 0.192 ;
    END
  END sum_o[188]
  PIN sum_o[189]
    DIRECTION OUTPUT ;
    USE SIGNAL ;
    PORT
      LAYER M5 ;
        RECT  28.128 0 28.152 0.192 ;
    END
  END sum_o[189]
  PIN sum_o[18]
    DIRECTION OUTPUT ;
    USE SIGNAL ;
    PORT
      LAYER M5 ;
        RECT  11.712 0 11.736 0.192 ;
    END
  END sum_o[18]
  PIN sum_o[190]
    DIRECTION OUTPUT ;
    USE SIGNAL ;
    PORT
      LAYER M5 ;
        RECT  28.224 0 28.248 0.192 ;
    END
  END sum_o[190]
  PIN sum_o[191]
    DIRECTION OUTPUT ;
    USE SIGNAL ;
    PORT
      LAYER M5 ;
        RECT  28.32 0 28.344 0.192 ;
    END
  END sum_o[191]
  PIN sum_o[192]
    DIRECTION OUTPUT ;
    USE SIGNAL ;
    PORT
      LAYER M5 ;
        RECT  28.416 0 28.44 0.192 ;
    END
  END sum_o[192]
  PIN sum_o[193]
    DIRECTION OUTPUT ;
    USE SIGNAL ;
    PORT
      LAYER M5 ;
        RECT  28.512 0 28.536 0.192 ;
    END
  END sum_o[193]
  PIN sum_o[194]
    DIRECTION OUTPUT ;
    USE SIGNAL ;
    PORT
      LAYER M5 ;
        RECT  28.608 0 28.632 0.192 ;
    END
  END sum_o[194]
  PIN sum_o[195]
    DIRECTION OUTPUT ;
    USE SIGNAL ;
    PORT
      LAYER M5 ;
        RECT  28.704 0 28.728 0.192 ;
    END
  END sum_o[195]
  PIN sum_o[196]
    DIRECTION OUTPUT ;
    USE SIGNAL ;
    PORT
      LAYER M5 ;
        RECT  28.8 0 28.824 0.192 ;
    END
  END sum_o[196]
  PIN sum_o[197]
    DIRECTION OUTPUT ;
    USE SIGNAL ;
    PORT
      LAYER M5 ;
        RECT  28.896 0 28.92 0.192 ;
    END
  END sum_o[197]
  PIN sum_o[198]
    DIRECTION OUTPUT ;
    USE SIGNAL ;
    PORT
      LAYER M5 ;
        RECT  28.992 0 29.016 0.192 ;
    END
  END sum_o[198]
  PIN sum_o[199]
    DIRECTION OUTPUT ;
    USE SIGNAL ;
    PORT
      LAYER M5 ;
        RECT  29.088 0 29.112 0.192 ;
    END
  END sum_o[199]
  PIN sum_o[19]
    DIRECTION OUTPUT ;
    USE SIGNAL ;
    PORT
      LAYER M5 ;
        RECT  11.808 0 11.832 0.192 ;
    END
  END sum_o[19]
  PIN sum_o[1]
    DIRECTION OUTPUT ;
    USE SIGNAL ;
    PORT
      LAYER M5 ;
        RECT  10.08 0 10.104 0.192 ;
    END
  END sum_o[1]
  PIN sum_o[200]
    DIRECTION OUTPUT ;
    USE SIGNAL ;
    PORT
      LAYER M5 ;
        RECT  29.184 0 29.208 0.192 ;
    END
  END sum_o[200]
  PIN sum_o[201]
    DIRECTION OUTPUT ;
    USE SIGNAL ;
    PORT
      LAYER M5 ;
        RECT  29.28 0 29.304 0.192 ;
    END
  END sum_o[201]
  PIN sum_o[202]
    DIRECTION OUTPUT ;
    USE SIGNAL ;
    PORT
      LAYER M5 ;
        RECT  29.376 0 29.4 0.192 ;
    END
  END sum_o[202]
  PIN sum_o[203]
    DIRECTION OUTPUT ;
    USE SIGNAL ;
    PORT
      LAYER M5 ;
        RECT  29.472 0 29.496 0.192 ;
    END
  END sum_o[203]
  PIN sum_o[204]
    DIRECTION OUTPUT ;
    USE SIGNAL ;
    PORT
      LAYER M5 ;
        RECT  29.568 0 29.592 0.192 ;
    END
  END sum_o[204]
  PIN sum_o[205]
    DIRECTION OUTPUT ;
    USE SIGNAL ;
    PORT
      LAYER M5 ;
        RECT  29.664 0 29.688 0.192 ;
    END
  END sum_o[205]
  PIN sum_o[206]
    DIRECTION OUTPUT ;
    USE SIGNAL ;
    PORT
      LAYER M5 ;
        RECT  29.76 0 29.784 0.192 ;
    END
  END sum_o[206]
  PIN sum_o[207]
    DIRECTION OUTPUT ;
    USE SIGNAL ;
    PORT
      LAYER M5 ;
        RECT  29.856 0 29.88 0.192 ;
    END
  END sum_o[207]
  PIN sum_o[208]
    DIRECTION OUTPUT ;
    USE SIGNAL ;
    PORT
      LAYER M5 ;
        RECT  29.952 0 29.976 0.192 ;
    END
  END sum_o[208]
  PIN sum_o[209]
    DIRECTION OUTPUT ;
    USE SIGNAL ;
    PORT
      LAYER M5 ;
        RECT  30.048 0 30.072 0.192 ;
    END
  END sum_o[209]
  PIN sum_o[20]
    DIRECTION OUTPUT ;
    USE SIGNAL ;
    PORT
      LAYER M5 ;
        RECT  11.904 0 11.928 0.192 ;
    END
  END sum_o[20]
  PIN sum_o[210]
    DIRECTION OUTPUT ;
    USE SIGNAL ;
    PORT
      LAYER M5 ;
        RECT  30.144 0 30.168 0.192 ;
    END
  END sum_o[210]
  PIN sum_o[211]
    DIRECTION OUTPUT ;
    USE SIGNAL ;
    PORT
      LAYER M5 ;
        RECT  30.24 0 30.264 0.192 ;
    END
  END sum_o[211]
  PIN sum_o[212]
    DIRECTION OUTPUT ;
    USE SIGNAL ;
    PORT
      LAYER M5 ;
        RECT  30.336 0 30.36 0.192 ;
    END
  END sum_o[212]
  PIN sum_o[213]
    DIRECTION OUTPUT ;
    USE SIGNAL ;
    PORT
      LAYER M5 ;
        RECT  30.432 0 30.456 0.192 ;
    END
  END sum_o[213]
  PIN sum_o[214]
    DIRECTION OUTPUT ;
    USE SIGNAL ;
    PORT
      LAYER M5 ;
        RECT  30.528 0 30.552 0.192 ;
    END
  END sum_o[214]
  PIN sum_o[215]
    DIRECTION OUTPUT ;
    USE SIGNAL ;
    PORT
      LAYER M5 ;
        RECT  30.624 0 30.648 0.192 ;
    END
  END sum_o[215]
  PIN sum_o[216]
    DIRECTION OUTPUT ;
    USE SIGNAL ;
    PORT
      LAYER M5 ;
        RECT  30.72 0 30.744 0.192 ;
    END
  END sum_o[216]
  PIN sum_o[217]
    DIRECTION OUTPUT ;
    USE SIGNAL ;
    PORT
      LAYER M5 ;
        RECT  30.816 0 30.84 0.192 ;
    END
  END sum_o[217]
  PIN sum_o[218]
    DIRECTION OUTPUT ;
    USE SIGNAL ;
    PORT
      LAYER M5 ;
        RECT  30.912 0 30.936 0.192 ;
    END
  END sum_o[218]
  PIN sum_o[219]
    DIRECTION OUTPUT ;
    USE SIGNAL ;
    PORT
      LAYER M5 ;
        RECT  31.008 0 31.032 0.192 ;
    END
  END sum_o[219]
  PIN sum_o[21]
    DIRECTION OUTPUT ;
    USE SIGNAL ;
    PORT
      LAYER M5 ;
        RECT  12 0 12.024 0.192 ;
    END
  END sum_o[21]
  PIN sum_o[220]
    DIRECTION OUTPUT ;
    USE SIGNAL ;
    PORT
      LAYER M5 ;
        RECT  31.104 0 31.128 0.192 ;
    END
  END sum_o[220]
  PIN sum_o[221]
    DIRECTION OUTPUT ;
    USE SIGNAL ;
    PORT
      LAYER M5 ;
        RECT  31.2 0 31.224 0.192 ;
    END
  END sum_o[221]
  PIN sum_o[222]
    DIRECTION OUTPUT ;
    USE SIGNAL ;
    PORT
      LAYER M5 ;
        RECT  31.296 0 31.32 0.192 ;
    END
  END sum_o[222]
  PIN sum_o[223]
    DIRECTION OUTPUT ;
    USE SIGNAL ;
    PORT
      LAYER M5 ;
        RECT  31.392 0 31.416 0.192 ;
    END
  END sum_o[223]
  PIN sum_o[224]
    DIRECTION OUTPUT ;
    USE SIGNAL ;
    PORT
      LAYER M5 ;
        RECT  31.488 0 31.512 0.192 ;
    END
  END sum_o[224]
  PIN sum_o[225]
    DIRECTION OUTPUT ;
    USE SIGNAL ;
    PORT
      LAYER M5 ;
        RECT  31.584 0 31.608 0.192 ;
    END
  END sum_o[225]
  PIN sum_o[226]
    DIRECTION OUTPUT ;
    USE SIGNAL ;
    PORT
      LAYER M5 ;
        RECT  31.68 0 31.704 0.192 ;
    END
  END sum_o[226]
  PIN sum_o[227]
    DIRECTION OUTPUT ;
    USE SIGNAL ;
    PORT
      LAYER M5 ;
        RECT  31.776 0 31.8 0.192 ;
    END
  END sum_o[227]
  PIN sum_o[228]
    DIRECTION OUTPUT ;
    USE SIGNAL ;
    PORT
      LAYER M5 ;
        RECT  31.872 0 31.896 0.192 ;
    END
  END sum_o[228]
  PIN sum_o[229]
    DIRECTION OUTPUT ;
    USE SIGNAL ;
    PORT
      LAYER M5 ;
        RECT  31.968 0 31.992 0.192 ;
    END
  END sum_o[229]
  PIN sum_o[22]
    DIRECTION OUTPUT ;
    USE SIGNAL ;
    PORT
      LAYER M5 ;
        RECT  12.096 0 12.12 0.192 ;
    END
  END sum_o[22]
  PIN sum_o[230]
    DIRECTION OUTPUT ;
    USE SIGNAL ;
    PORT
      LAYER M5 ;
        RECT  32.064 0 32.088 0.192 ;
    END
  END sum_o[230]
  PIN sum_o[231]
    DIRECTION OUTPUT ;
    USE SIGNAL ;
    PORT
      LAYER M5 ;
        RECT  32.16 0 32.184 0.192 ;
    END
  END sum_o[231]
  PIN sum_o[232]
    DIRECTION OUTPUT ;
    USE SIGNAL ;
    PORT
      LAYER M5 ;
        RECT  32.256 0 32.28 0.192 ;
    END
  END sum_o[232]
  PIN sum_o[233]
    DIRECTION OUTPUT ;
    USE SIGNAL ;
    PORT
      LAYER M5 ;
        RECT  32.352 0 32.376 0.192 ;
    END
  END sum_o[233]
  PIN sum_o[234]
    DIRECTION OUTPUT ;
    USE SIGNAL ;
    PORT
      LAYER M5 ;
        RECT  32.448 0 32.472 0.192 ;
    END
  END sum_o[234]
  PIN sum_o[235]
    DIRECTION OUTPUT ;
    USE SIGNAL ;
    PORT
      LAYER M5 ;
        RECT  32.544 0 32.568 0.192 ;
    END
  END sum_o[235]
  PIN sum_o[236]
    DIRECTION OUTPUT ;
    USE SIGNAL ;
    PORT
      LAYER M5 ;
        RECT  32.64 0 32.664 0.192 ;
    END
  END sum_o[236]
  PIN sum_o[237]
    DIRECTION OUTPUT ;
    USE SIGNAL ;
    PORT
      LAYER M5 ;
        RECT  32.736 0 32.76 0.192 ;
    END
  END sum_o[237]
  PIN sum_o[238]
    DIRECTION OUTPUT ;
    USE SIGNAL ;
    PORT
      LAYER M5 ;
        RECT  32.832 0 32.856 0.192 ;
    END
  END sum_o[238]
  PIN sum_o[239]
    DIRECTION OUTPUT ;
    USE SIGNAL ;
    PORT
      LAYER M5 ;
        RECT  32.928 0 32.952 0.192 ;
    END
  END sum_o[239]
  PIN sum_o[23]
    DIRECTION OUTPUT ;
    USE SIGNAL ;
    PORT
      LAYER M5 ;
        RECT  12.192 0 12.216 0.192 ;
    END
  END sum_o[23]
  PIN sum_o[240]
    DIRECTION OUTPUT ;
    USE SIGNAL ;
    PORT
      LAYER M5 ;
        RECT  33.024 0 33.048 0.192 ;
    END
  END sum_o[240]
  PIN sum_o[241]
    DIRECTION OUTPUT ;
    USE SIGNAL ;
    PORT
      LAYER M5 ;
        RECT  33.12 0 33.144 0.192 ;
    END
  END sum_o[241]
  PIN sum_o[242]
    DIRECTION OUTPUT ;
    USE SIGNAL ;
    PORT
      LAYER M5 ;
        RECT  33.216 0 33.24 0.192 ;
    END
  END sum_o[242]
  PIN sum_o[243]
    DIRECTION OUTPUT ;
    USE SIGNAL ;
    PORT
      LAYER M5 ;
        RECT  33.312 0 33.336 0.192 ;
    END
  END sum_o[243]
  PIN sum_o[244]
    DIRECTION OUTPUT ;
    USE SIGNAL ;
    PORT
      LAYER M5 ;
        RECT  33.408 0 33.432 0.192 ;
    END
  END sum_o[244]
  PIN sum_o[245]
    DIRECTION OUTPUT ;
    USE SIGNAL ;
    PORT
      LAYER M5 ;
        RECT  33.504 0 33.528 0.192 ;
    END
  END sum_o[245]
  PIN sum_o[246]
    DIRECTION OUTPUT ;
    USE SIGNAL ;
    PORT
      LAYER M5 ;
        RECT  33.6 0 33.624 0.192 ;
    END
  END sum_o[246]
  PIN sum_o[247]
    DIRECTION OUTPUT ;
    USE SIGNAL ;
    PORT
      LAYER M5 ;
        RECT  33.696 0 33.72 0.192 ;
    END
  END sum_o[247]
  PIN sum_o[248]
    DIRECTION OUTPUT ;
    USE SIGNAL ;
    PORT
      LAYER M5 ;
        RECT  33.792 0 33.816 0.192 ;
    END
  END sum_o[248]
  PIN sum_o[249]
    DIRECTION OUTPUT ;
    USE SIGNAL ;
    PORT
      LAYER M5 ;
        RECT  33.888 0 33.912 0.192 ;
    END
  END sum_o[249]
  PIN sum_o[24]
    DIRECTION OUTPUT ;
    USE SIGNAL ;
    PORT
      LAYER M5 ;
        RECT  12.288 0 12.312 0.192 ;
    END
  END sum_o[24]
  PIN sum_o[250]
    DIRECTION OUTPUT ;
    USE SIGNAL ;
    PORT
      LAYER M5 ;
        RECT  33.984 0 34.008 0.192 ;
    END
  END sum_o[250]
  PIN sum_o[251]
    DIRECTION OUTPUT ;
    USE SIGNAL ;
    PORT
      LAYER M5 ;
        RECT  34.08 0 34.104 0.192 ;
    END
  END sum_o[251]
  PIN sum_o[252]
    DIRECTION OUTPUT ;
    USE SIGNAL ;
    PORT
      LAYER M5 ;
        RECT  34.176 0 34.2 0.192 ;
    END
  END sum_o[252]
  PIN sum_o[253]
    DIRECTION OUTPUT ;
    USE SIGNAL ;
    PORT
      LAYER M5 ;
        RECT  34.272 0 34.296 0.192 ;
    END
  END sum_o[253]
  PIN sum_o[254]
    DIRECTION OUTPUT ;
    USE SIGNAL ;
    PORT
      LAYER M5 ;
        RECT  34.368 0 34.392 0.192 ;
    END
  END sum_o[254]
  PIN sum_o[255]
    DIRECTION OUTPUT ;
    USE SIGNAL ;
    PORT
      LAYER M5 ;
        RECT  34.464 0 34.488 0.192 ;
    END
  END sum_o[255]
  PIN sum_o[25]
    DIRECTION OUTPUT ;
    USE SIGNAL ;
    PORT
      LAYER M5 ;
        RECT  12.384 0 12.408 0.192 ;
    END
  END sum_o[25]
  PIN sum_o[26]
    DIRECTION OUTPUT ;
    USE SIGNAL ;
    PORT
      LAYER M5 ;
        RECT  12.48 0 12.504 0.192 ;
    END
  END sum_o[26]
  PIN sum_o[27]
    DIRECTION OUTPUT ;
    USE SIGNAL ;
    PORT
      LAYER M5 ;
        RECT  12.576 0 12.6 0.192 ;
    END
  END sum_o[27]
  PIN sum_o[28]
    DIRECTION OUTPUT ;
    USE SIGNAL ;
    PORT
      LAYER M5 ;
        RECT  12.672 0 12.696 0.192 ;
    END
  END sum_o[28]
  PIN sum_o[29]
    DIRECTION OUTPUT ;
    USE SIGNAL ;
    PORT
      LAYER M5 ;
        RECT  12.768 0 12.792 0.192 ;
    END
  END sum_o[29]
  PIN sum_o[2]
    DIRECTION OUTPUT ;
    USE SIGNAL ;
    PORT
      LAYER M5 ;
        RECT  10.176 0 10.2 0.192 ;
    END
  END sum_o[2]
  PIN sum_o[30]
    DIRECTION OUTPUT ;
    USE SIGNAL ;
    PORT
      LAYER M5 ;
        RECT  12.864 0 12.888 0.192 ;
    END
  END sum_o[30]
  PIN sum_o[31]
    DIRECTION OUTPUT ;
    USE SIGNAL ;
    PORT
      LAYER M5 ;
        RECT  12.96 0 12.984 0.192 ;
    END
  END sum_o[31]
  PIN sum_o[32]
    DIRECTION OUTPUT ;
    USE SIGNAL ;
    PORT
      LAYER M5 ;
        RECT  13.056 0 13.08 0.192 ;
    END
  END sum_o[32]
  PIN sum_o[33]
    DIRECTION OUTPUT ;
    USE SIGNAL ;
    PORT
      LAYER M5 ;
        RECT  13.152 0 13.176 0.192 ;
    END
  END sum_o[33]
  PIN sum_o[34]
    DIRECTION OUTPUT ;
    USE SIGNAL ;
    PORT
      LAYER M5 ;
        RECT  13.248 0 13.272 0.192 ;
    END
  END sum_o[34]
  PIN sum_o[35]
    DIRECTION OUTPUT ;
    USE SIGNAL ;
    PORT
      LAYER M5 ;
        RECT  13.344 0 13.368 0.192 ;
    END
  END sum_o[35]
  PIN sum_o[36]
    DIRECTION OUTPUT ;
    USE SIGNAL ;
    PORT
      LAYER M5 ;
        RECT  13.44 0 13.464 0.192 ;
    END
  END sum_o[36]
  PIN sum_o[37]
    DIRECTION OUTPUT ;
    USE SIGNAL ;
    PORT
      LAYER M5 ;
        RECT  13.536 0 13.56 0.192 ;
    END
  END sum_o[37]
  PIN sum_o[38]
    DIRECTION OUTPUT ;
    USE SIGNAL ;
    PORT
      LAYER M5 ;
        RECT  13.632 0 13.656 0.192 ;
    END
  END sum_o[38]
  PIN sum_o[39]
    DIRECTION OUTPUT ;
    USE SIGNAL ;
    PORT
      LAYER M5 ;
        RECT  13.728 0 13.752 0.192 ;
    END
  END sum_o[39]
  PIN sum_o[3]
    DIRECTION OUTPUT ;
    USE SIGNAL ;
    PORT
      LAYER M5 ;
        RECT  10.272 0 10.296 0.192 ;
    END
  END sum_o[3]
  PIN sum_o[40]
    DIRECTION OUTPUT ;
    USE SIGNAL ;
    PORT
      LAYER M5 ;
        RECT  13.824 0 13.848 0.192 ;
    END
  END sum_o[40]
  PIN sum_o[41]
    DIRECTION OUTPUT ;
    USE SIGNAL ;
    PORT
      LAYER M5 ;
        RECT  13.92 0 13.944 0.192 ;
    END
  END sum_o[41]
  PIN sum_o[42]
    DIRECTION OUTPUT ;
    USE SIGNAL ;
    PORT
      LAYER M5 ;
        RECT  14.016 0 14.04 0.192 ;
    END
  END sum_o[42]
  PIN sum_o[43]
    DIRECTION OUTPUT ;
    USE SIGNAL ;
    PORT
      LAYER M5 ;
        RECT  14.112 0 14.136 0.192 ;
    END
  END sum_o[43]
  PIN sum_o[44]
    DIRECTION OUTPUT ;
    USE SIGNAL ;
    PORT
      LAYER M5 ;
        RECT  14.208 0 14.232 0.192 ;
    END
  END sum_o[44]
  PIN sum_o[45]
    DIRECTION OUTPUT ;
    USE SIGNAL ;
    PORT
      LAYER M5 ;
        RECT  14.304 0 14.328 0.192 ;
    END
  END sum_o[45]
  PIN sum_o[46]
    DIRECTION OUTPUT ;
    USE SIGNAL ;
    PORT
      LAYER M5 ;
        RECT  14.4 0 14.424 0.192 ;
    END
  END sum_o[46]
  PIN sum_o[47]
    DIRECTION OUTPUT ;
    USE SIGNAL ;
    PORT
      LAYER M5 ;
        RECT  14.496 0 14.52 0.192 ;
    END
  END sum_o[47]
  PIN sum_o[48]
    DIRECTION OUTPUT ;
    USE SIGNAL ;
    PORT
      LAYER M5 ;
        RECT  14.592 0 14.616 0.192 ;
    END
  END sum_o[48]
  PIN sum_o[49]
    DIRECTION OUTPUT ;
    USE SIGNAL ;
    PORT
      LAYER M5 ;
        RECT  14.688 0 14.712 0.192 ;
    END
  END sum_o[49]
  PIN sum_o[4]
    DIRECTION OUTPUT ;
    USE SIGNAL ;
    PORT
      LAYER M5 ;
        RECT  10.368 0 10.392 0.192 ;
    END
  END sum_o[4]
  PIN sum_o[50]
    DIRECTION OUTPUT ;
    USE SIGNAL ;
    PORT
      LAYER M5 ;
        RECT  14.784 0 14.808 0.192 ;
    END
  END sum_o[50]
  PIN sum_o[51]
    DIRECTION OUTPUT ;
    USE SIGNAL ;
    PORT
      LAYER M5 ;
        RECT  14.88 0 14.904 0.192 ;
    END
  END sum_o[51]
  PIN sum_o[52]
    DIRECTION OUTPUT ;
    USE SIGNAL ;
    PORT
      LAYER M5 ;
        RECT  14.976 0 15 0.192 ;
    END
  END sum_o[52]
  PIN sum_o[53]
    DIRECTION OUTPUT ;
    USE SIGNAL ;
    PORT
      LAYER M5 ;
        RECT  15.072 0 15.096 0.192 ;
    END
  END sum_o[53]
  PIN sum_o[54]
    DIRECTION OUTPUT ;
    USE SIGNAL ;
    PORT
      LAYER M5 ;
        RECT  15.168 0 15.192 0.192 ;
    END
  END sum_o[54]
  PIN sum_o[55]
    DIRECTION OUTPUT ;
    USE SIGNAL ;
    PORT
      LAYER M5 ;
        RECT  15.264 0 15.288 0.192 ;
    END
  END sum_o[55]
  PIN sum_o[56]
    DIRECTION OUTPUT ;
    USE SIGNAL ;
    PORT
      LAYER M5 ;
        RECT  15.36 0 15.384 0.192 ;
    END
  END sum_o[56]
  PIN sum_o[57]
    DIRECTION OUTPUT ;
    USE SIGNAL ;
    PORT
      LAYER M5 ;
        RECT  15.456 0 15.48 0.192 ;
    END
  END sum_o[57]
  PIN sum_o[58]
    DIRECTION OUTPUT ;
    USE SIGNAL ;
    PORT
      LAYER M5 ;
        RECT  15.552 0 15.576 0.192 ;
    END
  END sum_o[58]
  PIN sum_o[59]
    DIRECTION OUTPUT ;
    USE SIGNAL ;
    PORT
      LAYER M5 ;
        RECT  15.648 0 15.672 0.192 ;
    END
  END sum_o[59]
  PIN sum_o[5]
    DIRECTION OUTPUT ;
    USE SIGNAL ;
    PORT
      LAYER M5 ;
        RECT  10.464 0 10.488 0.192 ;
    END
  END sum_o[5]
  PIN sum_o[60]
    DIRECTION OUTPUT ;
    USE SIGNAL ;
    PORT
      LAYER M5 ;
        RECT  15.744 0 15.768 0.192 ;
    END
  END sum_o[60]
  PIN sum_o[61]
    DIRECTION OUTPUT ;
    USE SIGNAL ;
    PORT
      LAYER M5 ;
        RECT  15.84 0 15.864 0.192 ;
    END
  END sum_o[61]
  PIN sum_o[62]
    DIRECTION OUTPUT ;
    USE SIGNAL ;
    PORT
      LAYER M5 ;
        RECT  15.936 0 15.96 0.192 ;
    END
  END sum_o[62]
  PIN sum_o[63]
    DIRECTION OUTPUT ;
    USE SIGNAL ;
    PORT
      LAYER M5 ;
        RECT  16.032 0 16.056 0.192 ;
    END
  END sum_o[63]
  PIN sum_o[64]
    DIRECTION OUTPUT ;
    USE SIGNAL ;
    PORT
      LAYER M5 ;
        RECT  16.128 0 16.152 0.192 ;
    END
  END sum_o[64]
  PIN sum_o[65]
    DIRECTION OUTPUT ;
    USE SIGNAL ;
    PORT
      LAYER M5 ;
        RECT  16.224 0 16.248 0.192 ;
    END
  END sum_o[65]
  PIN sum_o[66]
    DIRECTION OUTPUT ;
    USE SIGNAL ;
    PORT
      LAYER M5 ;
        RECT  16.32 0 16.344 0.192 ;
    END
  END sum_o[66]
  PIN sum_o[67]
    DIRECTION OUTPUT ;
    USE SIGNAL ;
    PORT
      LAYER M5 ;
        RECT  16.416 0 16.44 0.192 ;
    END
  END sum_o[67]
  PIN sum_o[68]
    DIRECTION OUTPUT ;
    USE SIGNAL ;
    PORT
      LAYER M5 ;
        RECT  16.512 0 16.536 0.192 ;
    END
  END sum_o[68]
  PIN sum_o[69]
    DIRECTION OUTPUT ;
    USE SIGNAL ;
    PORT
      LAYER M5 ;
        RECT  16.608 0 16.632 0.192 ;
    END
  END sum_o[69]
  PIN sum_o[6]
    DIRECTION OUTPUT ;
    USE SIGNAL ;
    PORT
      LAYER M5 ;
        RECT  10.56 0 10.584 0.192 ;
    END
  END sum_o[6]
  PIN sum_o[70]
    DIRECTION OUTPUT ;
    USE SIGNAL ;
    PORT
      LAYER M5 ;
        RECT  16.704 0 16.728 0.192 ;
    END
  END sum_o[70]
  PIN sum_o[71]
    DIRECTION OUTPUT ;
    USE SIGNAL ;
    PORT
      LAYER M5 ;
        RECT  16.8 0 16.824 0.192 ;
    END
  END sum_o[71]
  PIN sum_o[72]
    DIRECTION OUTPUT ;
    USE SIGNAL ;
    PORT
      LAYER M5 ;
        RECT  16.896 0 16.92 0.192 ;
    END
  END sum_o[72]
  PIN sum_o[73]
    DIRECTION OUTPUT ;
    USE SIGNAL ;
    PORT
      LAYER M5 ;
        RECT  16.992 0 17.016 0.192 ;
    END
  END sum_o[73]
  PIN sum_o[74]
    DIRECTION OUTPUT ;
    USE SIGNAL ;
    PORT
      LAYER M5 ;
        RECT  17.088 0 17.112 0.192 ;
    END
  END sum_o[74]
  PIN sum_o[75]
    DIRECTION OUTPUT ;
    USE SIGNAL ;
    PORT
      LAYER M5 ;
        RECT  17.184 0 17.208 0.192 ;
    END
  END sum_o[75]
  PIN sum_o[76]
    DIRECTION OUTPUT ;
    USE SIGNAL ;
    PORT
      LAYER M5 ;
        RECT  17.28 0 17.304 0.192 ;
    END
  END sum_o[76]
  PIN sum_o[77]
    DIRECTION OUTPUT ;
    USE SIGNAL ;
    PORT
      LAYER M5 ;
        RECT  17.376 0 17.4 0.192 ;
    END
  END sum_o[77]
  PIN sum_o[78]
    DIRECTION OUTPUT ;
    USE SIGNAL ;
    PORT
      LAYER M5 ;
        RECT  17.472 0 17.496 0.192 ;
    END
  END sum_o[78]
  PIN sum_o[79]
    DIRECTION OUTPUT ;
    USE SIGNAL ;
    PORT
      LAYER M5 ;
        RECT  17.568 0 17.592 0.192 ;
    END
  END sum_o[79]
  PIN sum_o[7]
    DIRECTION OUTPUT ;
    USE SIGNAL ;
    PORT
      LAYER M5 ;
        RECT  10.656 0 10.68 0.192 ;
    END
  END sum_o[7]
  PIN sum_o[80]
    DIRECTION OUTPUT ;
    USE SIGNAL ;
    PORT
      LAYER M5 ;
        RECT  17.664 0 17.688 0.192 ;
    END
  END sum_o[80]
  PIN sum_o[81]
    DIRECTION OUTPUT ;
    USE SIGNAL ;
    PORT
      LAYER M5 ;
        RECT  17.76 0 17.784 0.192 ;
    END
  END sum_o[81]
  PIN sum_o[82]
    DIRECTION OUTPUT ;
    USE SIGNAL ;
    PORT
      LAYER M5 ;
        RECT  17.856 0 17.88 0.192 ;
    END
  END sum_o[82]
  PIN sum_o[83]
    DIRECTION OUTPUT ;
    USE SIGNAL ;
    PORT
      LAYER M5 ;
        RECT  17.952 0 17.976 0.192 ;
    END
  END sum_o[83]
  PIN sum_o[84]
    DIRECTION OUTPUT ;
    USE SIGNAL ;
    PORT
      LAYER M5 ;
        RECT  18.048 0 18.072 0.192 ;
    END
  END sum_o[84]
  PIN sum_o[85]
    DIRECTION OUTPUT ;
    USE SIGNAL ;
    PORT
      LAYER M5 ;
        RECT  18.144 0 18.168 0.192 ;
    END
  END sum_o[85]
  PIN sum_o[86]
    DIRECTION OUTPUT ;
    USE SIGNAL ;
    PORT
      LAYER M5 ;
        RECT  18.24 0 18.264 0.192 ;
    END
  END sum_o[86]
  PIN sum_o[87]
    DIRECTION OUTPUT ;
    USE SIGNAL ;
    PORT
      LAYER M5 ;
        RECT  18.336 0 18.36 0.192 ;
    END
  END sum_o[87]
  PIN sum_o[88]
    DIRECTION OUTPUT ;
    USE SIGNAL ;
    PORT
      LAYER M5 ;
        RECT  18.432 0 18.456 0.192 ;
    END
  END sum_o[88]
  PIN sum_o[89]
    DIRECTION OUTPUT ;
    USE SIGNAL ;
    PORT
      LAYER M5 ;
        RECT  18.528 0 18.552 0.192 ;
    END
  END sum_o[89]
  PIN sum_o[8]
    DIRECTION OUTPUT ;
    USE SIGNAL ;
    PORT
      LAYER M5 ;
        RECT  10.752 0 10.776 0.192 ;
    END
  END sum_o[8]
  PIN sum_o[90]
    DIRECTION OUTPUT ;
    USE SIGNAL ;
    PORT
      LAYER M5 ;
        RECT  18.624 0 18.648 0.192 ;
    END
  END sum_o[90]
  PIN sum_o[91]
    DIRECTION OUTPUT ;
    USE SIGNAL ;
    PORT
      LAYER M5 ;
        RECT  18.72 0 18.744 0.192 ;
    END
  END sum_o[91]
  PIN sum_o[92]
    DIRECTION OUTPUT ;
    USE SIGNAL ;
    PORT
      LAYER M5 ;
        RECT  18.816 0 18.84 0.192 ;
    END
  END sum_o[92]
  PIN sum_o[93]
    DIRECTION OUTPUT ;
    USE SIGNAL ;
    PORT
      LAYER M5 ;
        RECT  18.912 0 18.936 0.192 ;
    END
  END sum_o[93]
  PIN sum_o[94]
    DIRECTION OUTPUT ;
    USE SIGNAL ;
    PORT
      LAYER M5 ;
        RECT  19.008 0 19.032 0.192 ;
    END
  END sum_o[94]
  PIN sum_o[95]
    DIRECTION OUTPUT ;
    USE SIGNAL ;
    PORT
      LAYER M5 ;
        RECT  19.104 0 19.128 0.192 ;
    END
  END sum_o[95]
  PIN sum_o[96]
    DIRECTION OUTPUT ;
    USE SIGNAL ;
    PORT
      LAYER M5 ;
        RECT  19.2 0 19.224 0.192 ;
    END
  END sum_o[96]
  PIN sum_o[97]
    DIRECTION OUTPUT ;
    USE SIGNAL ;
    PORT
      LAYER M5 ;
        RECT  19.296 0 19.32 0.192 ;
    END
  END sum_o[97]
  PIN sum_o[98]
    DIRECTION OUTPUT ;
    USE SIGNAL ;
    PORT
      LAYER M5 ;
        RECT  19.392 0 19.416 0.192 ;
    END
  END sum_o[98]
  PIN sum_o[99]
    DIRECTION OUTPUT ;
    USE SIGNAL ;
    PORT
      LAYER M5 ;
        RECT  19.488 0 19.512 0.192 ;
    END
  END sum_o[99]
  PIN sum_o[9]
    DIRECTION OUTPUT ;
    USE SIGNAL ;
    PORT
      LAYER M5 ;
        RECT  10.848 0 10.872 0.192 ;
    END
  END sum_o[9]
  PIN VDD
    DIRECTION INOUT ;
    USE POWER ;
    PORT
      LAYER M6 ;
        RECT  0.468 111.32 85.932 111.608 ;
        RECT  0.468 100.52 85.932 100.808 ;
        RECT  0.468 89.72 85.932 90.008 ;
        RECT  0.468 78.92 85.932 79.208 ;
        RECT  0.468 68.12 85.932 68.408 ;
        RECT  0.468 57.32 85.932 57.608 ;
        RECT  0.468 46.52 85.932 46.808 ;
        RECT  0.468 35.72 85.932 36.008 ;
        RECT  0.468 24.92 85.932 25.208 ;
        RECT  0.468 14.12 85.932 14.408 ;
        RECT  0.468 3.32 85.932 3.608 ;
        RECT  0.468 119.484 85.932 119.772 ;
        RECT  0.468 0.108 85.932 0.396 ;
    END
  END VDD
  PIN VSS
    DIRECTION INOUT ;
    USE GROUND ;
    PORT
      LAYER M6 ;
        RECT  0.468 110.936 85.932 111.224 ;
        RECT  0.468 100.136 85.932 100.424 ;
        RECT  0.468 89.336 85.932 89.624 ;
        RECT  0.468 78.536 85.932 78.824 ;
        RECT  0.468 67.736 85.932 68.024 ;
        RECT  0.468 56.936 85.932 57.224 ;
        RECT  0.468 46.136 85.932 46.424 ;
        RECT  0.468 35.336 85.932 35.624 ;
        RECT  0.468 24.536 85.932 24.824 ;
        RECT  0.468 13.736 85.932 14.024 ;
        RECT  0.468 2.936 85.932 3.224 ;
        RECT  0.66 119.1 85.74 119.388 ;
        RECT  0.66 0.492 85.74 0.78 ;
    END
  END VSS
  OBS
    LAYER RVTN ;
     RECT  0.468 0 85.932 120.024 ;
    LAYER RVTP ;
     RECT  0.468 0 85.932 120.024 ;
    LAYER M1 ;
     RECT  0.468 0 85.932 120.024 ;
    LAYER M2 ;
     RECT  0.468 0 85.932 120.024 ;
    LAYER M3 ;
     RECT  0.468 0 85.932 120.024 ;
    LAYER M4 ;
     RECT  0.468 0 85.932 120.024 ;
    LAYER M5 ;
     RECT  0.468 0 85.932 120.024 ;
    LAYER M6 ;
     RECT  0.468 0 85.932 120.024 ;
  END
END ot_hbm_accel_smh_tcl
END LIBRARY
